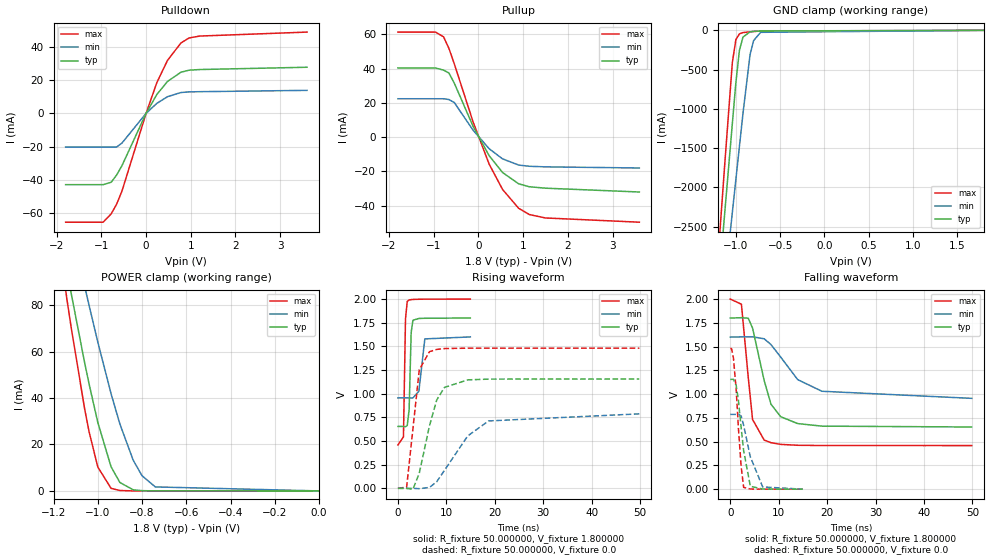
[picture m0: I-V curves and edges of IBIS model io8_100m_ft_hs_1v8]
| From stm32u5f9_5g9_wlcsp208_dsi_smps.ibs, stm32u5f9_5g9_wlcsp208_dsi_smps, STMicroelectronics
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|   Model io8_100m_ft_hs_1v8
[Model]  io8_100m_ft_hs_1v8
Model_type I/O
Polarity   Non-Inverting
Enable   Active-Low
Vinl =   0.540000V
Vinh =   1.260000V
Vmeas =  0.900000V
Cref =   50.000000pF
Rref =   100.000000M
Vref =   0.0V
C_comp   3.148300pF   3.147400pF   3.196500pF
[Temperature Range]   25.000000   0.140000k   -40.000000
[Pullup Reference]   1.800000V   1.600000V   2.000000V
[Pulldown Reference]   0.0V   0.0V   0.0V
[POWER Clamp Reference]   1.800000V   1.600000V   2.000000V
[GND Clamp Reference]   0.0V   0.0V   0.0V
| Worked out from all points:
|   slope of the pulldown table from 0 to 0.27 V, typ, clamps not added: 21.7 ohm
|   slope of the pullup table from 0 to 0.27 V, typ, clamps not added: 22.6 ohm
|   GND clamp passes 1 mA (typ) near -0.51 V on its own axis
|   POWER clamp passes 1 mA (typ) near -0.86 V on its own axis
|   rising waveform, R_fixture 50.000000, V_fixture 1.800000: 20-80 % time 321ps typ, 632ps min, 233ps max; typ from 0.654 V to 1.8 V
|   rising waveform, R_fixture 50.000000, V_fixture 0.0: 20-80 % time 3.21ns typ, 6.76ns min, 1.69ns max; typ from 0 V to 1.16 V
|   falling waveform, R_fixture 50.000000, V_fixture 1.800000: 20-80 % time 3.21ns typ, 6.73ns min, 1.65ns max; typ from 1.8 V to 0.654 V
|   falling waveform, R_fixture 50.000000, V_fixture 0.0: 20-80 % time 1.6ns typ, 2.38ns min, 1.14ns max; typ from 1.16 V to 0 V
[Pulldown]
|Voltage   I(typ)   I(min)   I(max)
-1.8V     -42.74mA   -20.21mA   -65.25mA
-960mV    -42.74mA   -20.21mA   -65.25mA
-780mV    -41.3mA    -20.21mA   -60.25mA
-660mV    -37mA      -20.2mA    -54.5mA
-540mV    -31.39mA   -17.82mA   -46.65mA
0V        0A         0A         10fA
240mV     11.28mA    6.002mA    18.38mA
480mV     19.18mA    10.02mA    31.83mA
780mV     24.67mA    12.5mA     42.21mA
960mV     25.9mA     12.9mA     45.21mA
1.2V      26.29mA    13.01mA    46.37mA
3.6V      27.67mA    13.81mA    48.75mA
[Pullup]
|Voltage   I(typ)   I(min)   I(max)
-1.8V     40.33mA    22.37mA    61.24mA
-960mV    40.33mA    22.37mA    61.24mA
-780mV    39.05mA    22.37mA    58.49mA
-660mV    37.4mA     21.92mA    51.77mA
-540mV    31.51mA    20.18mA    42.78mA
-120mV    6.338mA    4.065mA    8.965mA
240mV     -10.82mA   -6.752mA   -15.73mA
540mV     -20.62mA   -12.68mA   -30.5mA
900mV     -27.22mA   -16.28mA   -41.49mA
1.14V     -28.94mA   -17mA      -45.14mA
1.5V      -29.77mA   -17.34mA   -47.14mA
3.6V      -32mA      -18mA      -49.6mA
[GND_clamp]
|Voltage   I(typ)   I(min)   I(max)
-1.8V     -9.707A    -9.942A    -9.774A
-1.2V     -3.309A    -4.006A    -2.864A
-1.16V    -2.777A    -3.584A    -2.239A
-1.12V    -2.246A    -3.162A    -1.614A
-1.04V    -1.186A    -2.319A    -408.6mA
-1V       -663.9mA   -1.898A    -117.8mA
-960mV    -254mA     -1.478A    -45.14mA
-920mV    -86.03mA   -1.06A     -28.58mA
-840mV    -19.12mA   -308.9mA   -18.74mA
-800mV    -13.39mA   -130.8mA   -15.31mA
-720mV    -7.948mA   -25.37mA   -9.381mA
1.8V      0A         14.97nA    0A
[POWER_clamp]
|Voltage   I(typ)   I(min)   I(max)
-1.8V     470.8mA    433.7mA    554.6mA
-1.14V    95.25mA    122.7mA    82.82mA
-1.12V    84.97mA    114mA      70.27mA
-1.06V    55.51mA    88.42mA    35.67mA
-1.04V    46.34mA    80.15mA    25.76mA
-1V       29.51mA    64.13mA    10.3mA
-940mV    10.39mA    41.86mA    1.109mA
-900mV    3.624mA    28.77mA    182.8uA
-840mV    490.7uA    13.24mA    11.35uA
-800mV    116.8uA    6.532mA    1.77uA
-740mV    13.2uA     1.723mA    109.3nA
0V        0A         18.72nA    0A
[Ramp]
| variable   typ   min   max
dV/dt_r  0.69300/3.20236n   0.47203/6.75416n   0.88872/1.68887n
dV/dt_f  0.68762/3.20647n   0.38659/6.71804n   0.92482/1.65085n
R_load = 50.000000
[Rising Waveform]
R_fixture= 50.000000
V_fixture= 1.800000
V_fixture_min= 1.600000
V_fixture_max= 2.000000
|time   V(typ)   V(min)   V(max)
0s        654mV      955.4mV    458.7mV
1.141ns   653.9mV    955.4mV    543.2mV
1.562ns   650.9mV    955.4mV    1.79V
1.922ns   663.7mV    955.4mV    1.975V
2.312ns   831.7mV    955.4mV    1.99V
2.733ns   1.646V     955.2mV    1.994V
3.093ns   1.776V     954.4mV    1.996V
4.324ns   1.795V     1.026V     1.998V
5.556ns   1.797V     1.579V     1.999V
14.95ns   1.8V       1.6V       2V
[Rising Waveform]
R_fixture= 50.000000
V_fixture= 0.0
V_fixture_min= 0.0
V_fixture_max= 0.0
|time   V(typ)   V(min)   V(max)
0s        3.153uV    2.99uV     1.193uV
1.802ns   -1.584mV   522.9nV    12.74mV
3.103ns   -9.118mV   131.7uV    631.6mV
4.404ns   157.9mV    -4.26mV    1.252V
6.507ns   658.7mV    9.256mV    1.444V
8.008ns   933.8mV    69.31mV    1.468V
9.61ns    1.066V     190mV      1.477V
14.41ns   1.146V     553.5mV    1.481V
18.72ns   1.154V     712mV      1.481V
49.85ns   1.155V     786.8mV    1.481V
[Falling Waveform]
R_fixture= 50.000000
V_fixture= 1.800000
V_fixture_min= 1.600000
V_fixture_max= 2.000000
|time   V(typ)   V(min)   V(max)
0s        1.8V       1.6V       2V
2.302ns   1.804V     1.602V     1.946V
3.704ns   1.799V     1.603V     1.182V
4.605ns   1.695V     1.603V     733.4mV
7.007ns   1.142V     1.582V     516mV
8.408ns   894mV      1.521V     489mV
10.41ns   762.2mV    1.39V      471.2mV
13.91ns   690.1mV    1.153V     461.8mV
18.92ns   663.1mV    1.03V      459.1mV
49.85ns   654mV      955.4mV    458.7mV
[Falling Waveform]
R_fixture= 50.000000
V_fixture= 0.0
V_fixture_min= 0.0
V_fixture_max= 0.0
|time   V(typ)   V(min)   V(max)
0s        1.155V     786.8mV    1.481V
270.3ps   1.155V     786.8mV    1.479V
660.7ps   1.156V     786.8mV    1.376V
1.231ns   1.09V      786.7mV    1.043V
1.682ns   935.3mV    787.7mV    643.2mV
2.252ns   645.8mV    770.1mV    235.1mV
2.763ns   405.4mV    671.5mV    19.03mV
4.144ns   30.19mV    340mV      1.495mV
6.697ns   1.145mV    23.21mV    456.7uV
14.95ns   3.153uV    2.99uV     1.193uV
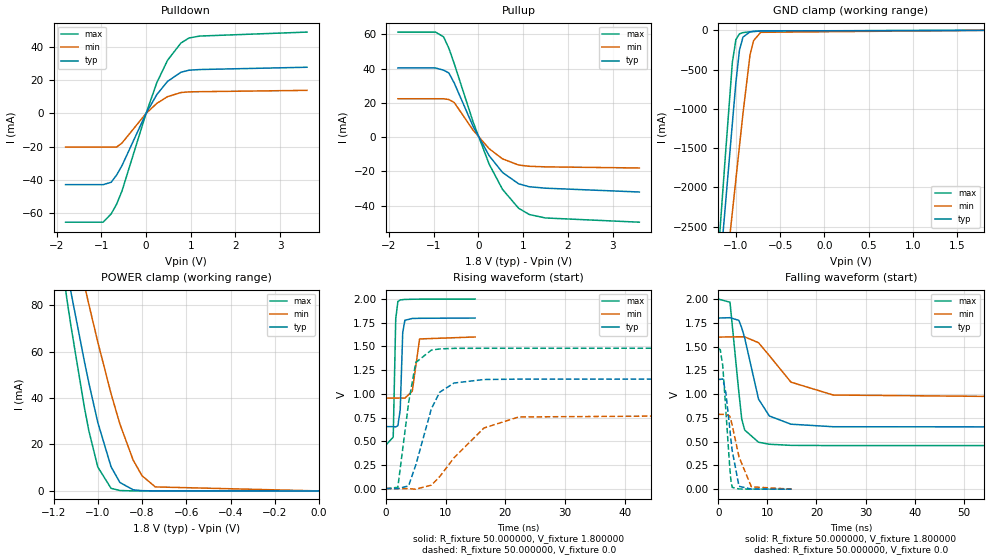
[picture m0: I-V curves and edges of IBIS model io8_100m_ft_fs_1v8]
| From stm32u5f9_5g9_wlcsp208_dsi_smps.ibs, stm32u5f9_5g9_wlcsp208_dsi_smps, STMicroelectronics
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|   Model io8_100m_ft_fs_1v8
[Model]  io8_100m_ft_fs_1v8
Model_type I/O
Polarity   Non-Inverting
Enable   Active-Low
Vinl =   0.540000V
Vinh =   1.260000V
Vmeas =  0.900000V
Cref =   50.000000pF
Rref =   100.000000M
Vref =   0.0V
C_comp   3.148300pF   3.147400pF   3.196500pF
[Temperature Range]   25.000000   0.140000k   -40.000000
[Pullup Reference]   1.800000V   1.600000V   2.000000V
[Pulldown Reference]   0.0V   0.0V   0.0V
[POWER Clamp Reference]   1.800000V   1.600000V   2.000000V
[GND Clamp Reference]   0.0V   0.0V   0.0V
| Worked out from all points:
|   slope of the pulldown table from 0 to 0.27 V, typ, clamps not added: 21.7 ohm
|   slope of the pullup table from 0 to 0.27 V, typ, clamps not added: 22.6 ohm
|   GND clamp passes 1 mA (typ) near -0.51 V on its own axis
|   POWER clamp passes 1 mA (typ) near -0.86 V on its own axis
|   rising waveform, R_fixture 50.000000, V_fixture 1.800000: 20-80 % time 321ps typ, 632ps min, 233ps max; typ from 0.654 V to 1.8 V
|   rising waveform, R_fixture 50.000000, V_fixture 0.0: 20-80 % time 3.21ns typ, 6.76ns min, 1.69ns max; typ from 0 V to 1.16 V
|   falling waveform, R_fixture 50.000000, V_fixture 1.800000: 20-80 % time 3.21ns typ, 6.73ns min, 1.66ns max; typ from 1.8 V to 0.654 V
|   falling waveform, R_fixture 50.000000, V_fixture 0.0: 20-80 % time 1.6ns typ, 2.38ns min, 1.14ns max; typ from 1.16 V to 0 V
[Pulldown]
|Voltage   I(typ)   I(min)   I(max)
-1.8V     -42.74mA   -20.21mA   -65.25mA
-960mV    -42.74mA   -20.21mA   -65.25mA
-780mV    -41.3mA    -20.21mA   -60.25mA
-660mV    -37mA      -20.2mA    -54.5mA
-540mV    -31.39mA   -17.82mA   -46.65mA
0V        0A         0A         10fA
240mV     11.28mA    6.002mA    18.38mA
480mV     19.18mA    10.02mA    31.83mA
780mV     24.67mA    12.5mA     42.21mA
960mV     25.9mA     12.9mA     45.21mA
1.2V      26.29mA    13.01mA    46.37mA
3.6V      27.67mA    13.81mA    48.75mA
[Pullup]
|Voltage   I(typ)   I(min)   I(max)
-1.8V     40.33mA    22.37mA    61.24mA
-960mV    40.33mA    22.37mA    61.24mA
-780mV    39.05mA    22.37mA    58.49mA
-660mV    37.4mA     21.92mA    51.77mA
-540mV    31.51mA    20.18mA    42.78mA
-120mV    6.338mA    4.065mA    8.965mA
240mV     -10.82mA   -6.752mA   -15.73mA
540mV     -20.62mA   -12.68mA   -30.5mA
900mV     -27.22mA   -16.28mA   -41.49mA
1.14V     -28.94mA   -17mA      -45.14mA
1.5V      -29.77mA   -17.34mA   -47.14mA
3.6V      -32mA      -18mA      -49.6mA
[GND_clamp]
|Voltage   I(typ)   I(min)   I(max)
-1.8V     -9.707A    -9.942A    -9.774A
-1.2V     -3.309A    -4.006A    -2.864A
-1.16V    -2.777A    -3.584A    -2.239A
-1.12V    -2.246A    -3.162A    -1.614A
-1.04V    -1.186A    -2.319A    -408.6mA
-1V       -663.9mA   -1.898A    -117.8mA
-960mV    -254mA     -1.478A    -45.14mA
-920mV    -86.03mA   -1.06A     -28.58mA
-840mV    -19.12mA   -308.9mA   -18.74mA
-800mV    -13.39mA   -130.8mA   -15.31mA
-720mV    -7.948mA   -25.37mA   -9.381mA
1.8V      0A         14.97nA    0A
[POWER_clamp]
|Voltage   I(typ)   I(min)   I(max)
-1.8V     470.8mA    433.7mA    554.6mA
-1.14V    95.25mA    122.7mA    82.82mA
-1.12V    84.97mA    114mA      70.27mA
-1.06V    55.51mA    88.42mA    35.67mA
-1.04V    46.34mA    80.15mA    25.76mA
-1V       29.51mA    64.13mA    10.3mA
-940mV    10.39mA    41.86mA    1.109mA
-900mV    3.624mA    28.77mA    182.8uA
-840mV    490.7uA    13.24mA    11.35uA
-800mV    116.8uA    6.532mA    1.77uA
-740mV    13.2uA     1.723mA    109.3nA
0V        0A         18.72nA    0A
[Ramp]
| variable   typ   min   max
dV/dt_r  0.69306/3.20389n   0.47207/6.75528n   0.88872/1.68920n
dV/dt_f  0.68762/3.20632n   0.38677/6.72664n   0.92482/1.65073n
R_load = 50.000000
[Rising Waveform]
R_fixture= 50.000000
V_fixture= 1.800000
V_fixture_min= 1.600000
V_fixture_max= 2.000000
|time   V(typ)   V(min)   V(max)
0s        654mV      955.4mV    458.7mV
1.231ns   653.9mV    955.4mV    543.2mV
1.652ns   650.9mV    955.4mV    1.79V
2.012ns   663.7mV    955.4mV    1.975V
2.402ns   831.7mV    955.4mV    1.99V
2.823ns   1.646V     955.2mV    1.994V
3.183ns   1.776V     954.4mV    1.996V
4.414ns   1.795V     1.026V     1.998V
5.646ns   1.797V     1.579V     1.999V
14.95ns   1.8V       1.6V       2V
[Rising Waveform]
R_fixture= 50.000000
V_fixture= 0.0
V_fixture_min= 0.0
V_fixture_max= 0.0
|time   V(typ)   V(min)   V(max)
0s        3.637uV    3.111uV    2.587uV
2.002ns   -1.584mV   523.3nV    12.74mV
3.804ns   28.7mV     -635.9uV   905.6mV
5.005ns   248.3mV    -6.203mV   1.331V
7.608ns   840.1mV    36.16mV    1.461V
9.009ns   1.017V     125.6mV    1.474V
11.41ns   1.114V     325.4mV    1.48V
16.42ns   1.151V     639.3mV    1.481V
22.22ns   1.155V     755.7mV    1.481V
99.7ns    1.155V     786.8mV    1.481V
[Falling Waveform]
R_fixture= 50.000000
V_fixture= 1.800000
V_fixture_min= 1.600000
V_fixture_max= 2.000000
|time   V(typ)   V(min)   V(max)
0s        1.8V       1.6V       2V
2.402ns   1.804V     1.602V     1.967V
4.204ns   1.776V     1.603V     1.02V
4.805ns   1.695V     1.603V     733.4mV
5.405ns   1.588V     1.602V     621.5mV
8.208ns   948mV      1.541V     494.3mV
10.41ns   770mV      1.405V     472.6mV
14.81ns   683.5mV    1.126V     460.9mV
23.42ns   656.8mV    990.4mV    458.7mV
99.7ns    654mV      955.4mV    458.7mV
[Falling Waveform]
R_fixture= 50.000000
V_fixture= 0.0
V_fixture_min= 0.0
V_fixture_max= 0.0
|time   V(typ)   V(min)   V(max)
0s        1.155V     786.8mV    1.481V
420.4ps   1.155V     786.8mV    1.468V
930.9ps   1.16V      786.8mV    1.298V
1.562ns   1.015V     786.6mV    826.2mV
2.342ns   645.8mV    770.1mV    235.1mV
2.613ns   508.9mV    723.1mV    80.64mV
2.853ns   405.4mV    671.5mV    19.03mV
4.234ns   30.18mV    340mV      1.495mV
6.757ns   1.156mV    24.78mV    463.3uV
14.95ns   3.637uV    3.111uV    2.587uV
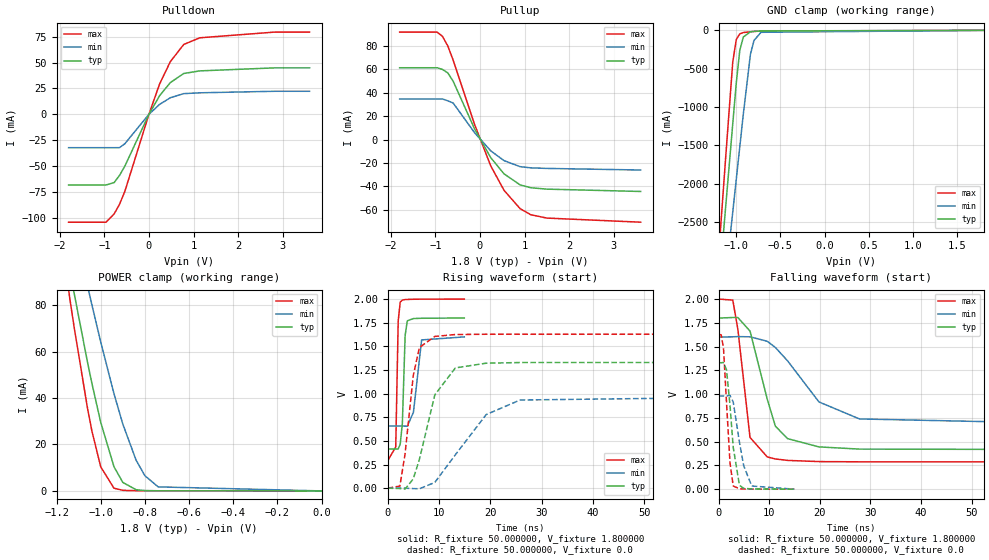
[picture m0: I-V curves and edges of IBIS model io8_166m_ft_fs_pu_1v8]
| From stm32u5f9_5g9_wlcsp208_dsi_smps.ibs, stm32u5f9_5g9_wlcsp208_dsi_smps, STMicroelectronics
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|   Model io8_166m_ft_fs_pu_1v8
[Model]  io8_166m_ft_fs_pu_1v8
Model_type I/O
Polarity   Non-Inverting
Enable   Active-Low
Vinl =   0.540000V
Vinh =   1.260000V
Vmeas =  0.900000V
Cref =   50.000000pF
Rref =   100.000000M
Vref =   0.0V
C_comp   3.358200pF   3.352700pF   3.400300pF
[Temperature Range]   25.000000   0.140000k   -40.000000
[Pullup Reference]   1.800000V   1.600000V   2.000000V
[Pulldown Reference]   0.0V   0.0V   0.0V
[POWER Clamp Reference]   1.800000V   1.600000V   2.000000V
[GND Clamp Reference]   0.0V   0.0V   0.0V
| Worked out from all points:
|   slope of the pulldown table from 0 to 0.27 V, typ, clamps not added: 13.6 ohm
|   slope of the pullup table from 0 to 0.27 V, typ, clamps not added: 15.9 ohm
|   GND clamp passes 1 mA (typ) near -0.51 V on its own axis
|   POWER clamp passes 1 mA (typ) near -0.86 V on its own axis
|   rising waveform, R_fixture 50.000000, V_fixture 1.800000: 20-80 % time 454ps typ, 903ps min, 301ps max; typ from 0.414 V to 1.8 V
|   rising waveform, R_fixture 50.000000, V_fixture 0.0: 20-80 % time 3.64ns typ, 7.99ns min, 1.94ns max; typ from 0 V to 1.33 V
|   falling waveform, R_fixture 50.000000, V_fixture 1.800000: 20-80 % time 3.87ns typ, 9.14ns min, 2.06ns max; typ from 1.8 V to 0.414 V
|   falling waveform, R_fixture 50.000000, V_fixture 0.0: 20-80 % time 1.32ns typ, 1.87ns min, 984ps max; typ from 1.33 V to 0 V
[Pulldown]
|Voltage   I(typ)   I(min)   I(max)
-1.8V     -68.38mA   -32.32mA   -104.4mA
-960mV    -68.38mA   -32.32mA   -104.4mA
-780mV    -66.08mA   -32.32mA   -96.43mA
-660mV    -59.2mA    -32.31mA   -87.22mA
-540mV    -50.22mA   -28.51mA   -74.66mA
0V        0A         0A         0A
240mV     18.04mA    9.6mA      29.42mA
480mV     30.68mA    16.02mA    50.95mA
780mV     39.48mA    19.99mA    67.56mA
1.14V     41.99mA    20.78mA    74.01mA
2.82V     44.92mA    22.27mA    79.53mA
3.6V      44.92mA    22.27mA    79.53mA
[Pullup]
|Voltage   I(typ)   I(min)   I(max)
-1.8V     61.22mA    34.57mA    91.63mA
-960mV    61.22mA    34.57mA    91.63mA
-840mV    59.78mA    34.57mA    88mA
-720mV    56.81mA    33.01mA    79.76mA
-600mV    49.68mA    31.1mA     67.63mA
-120mV    9.014mA    5.781mA    12.75mA
240mV     -15.38mA   -9.6mA     -22.37mA
540mV     -29.31mA   -18.02mA   -43.36mA
900mV     -38.69mA   -23.13mA   -58.99mA
1.14V     -41.14mA   -24.16mA   -64.17mA
1.5V      -42.31mA   -24.64mA   -67mA
3.6V      -44.3mA    -26mA      -70.5mA
[GND_clamp]
|Voltage   I(typ)   I(min)   I(max)
-1.8V     -9.908A    -9.683A    -9.994A
-1.2V     -3.383A    -4.084A    -2.934A
-1.16V    -2.841A    -3.655A    -2.294A
-1.12V    -2.299A    -3.226A    -1.656A
-1.04V    -1.218A    -2.369A    -414.2mA
-1V       -684.7mA   -1.941A    -119.2mA
-960mV    -257.2mA   -1.514A    -45.66mA
-920mV    -87.03mA   -1.089A    -28.93mA
-840mV    -19.35mA   -312.8mA   -18.97mA
-800mV    -13.55mA   -132.4mA   -15.49mA
-720mV    -8.042mA   -25.67mA   -9.491mA
1.8V      0A         13.64nA    0A
[POWER_clamp]
|Voltage   I(typ)   I(min)   I(max)
-1.8V     470.9mA    433.7mA    554.6mA
-1.14V    95.28mA    122.7mA    82.88mA
-1.12V    85mA       114mA      70.34mA
-1.06V    55.55mA    88.43mA    35.73mA
-1.04V    46.38mA    80.17mA    25.83mA
-1V       29.54mA    64.14mA    10.37mA
-940mV    10.43mA    41.88mA    1.177mA
-900mV    3.66mA     28.79mA    250.5uA
-840mV    527.2uA    13.26mA    95.94uA
-800mV    154uA      6.55mA     88.4uA
-740mV    59.84uA    1.741mA    70.38uA
0V        0A         18.18nA    0A
[Ramp]
| variable   typ   min   max
dV/dt_r  0.79757/3.63113n   0.58806/7.98205n   0.97651/1.93368n
dV/dt_f  0.83132/3.86660n   0.56553/9.12592n   1.02743/2.04826n
R_load = 50.000000
[Rising Waveform]
R_fixture= 50.000000
V_fixture= 1.800000
V_fixture_min= 1.600000
V_fixture_max= 2.000000
|time   V(typ)   V(min)   V(max)
0s        414.4mV    657.5mV    287.6mV
1.592ns   413.9mV    657.5mV    436mV
2.072ns   415.6mV    657.5mV    1.767V
2.462ns   464.5mV    657.5mV    1.968V
2.883ns   686.6mV    657.4mV    1.989V
3.423ns   1.615V     656.5mV    1.995V
3.844ns   1.77V      655mV      1.996V
5.045ns   1.794V     804.6mV    1.998V
6.637ns   1.797V     1.568V     1.999V
14.95ns   1.8V       1.6V       2V
[Rising Waveform]
R_fixture= 50.000000
V_fixture= 0.0
V_fixture_min= 0.0
V_fixture_max= 0.0
|time   V(typ)   V(min)   V(max)
0s        427.6uV    510uV      389.5uV
2.402ns   -3.279mV   508.5uV    23.12mV
3.403ns   -9.971mV   612.4uV    361.2mV
5.005ns   98.92mV    -3.813mV   1.191V
6.206ns   305.4mV    -6.052mV   1.488V
9.209ns   987.3mV    61.44mV    1.605V
13.21ns   1.272V     353.7mV    1.625V
19.22ns   1.322V     779.1mV    1.628V
25.83ns   1.329V     932.8mV    1.628V
99.7ns    1.33V      980.7mV    1.628V
[Falling Waveform]
R_fixture= 50.000000
V_fixture= 1.800000
V_fixture_min= 1.600000
V_fixture_max= 2.000000
|time   V(typ)   V(min)   V(max)
0s        1.8V       1.6V       2V
2.803ns   1.806V     1.603V     1.989V
3.804ns   1.806V     1.605V     1.682V
6.206ns   1.663V     1.603V     544.2mV
9.61ns    946.3mV    1.556V     339.6mV
11.21ns   663.2mV    1.491V     318mV
13.61ns   532.2mV    1.351V     303mV
19.82ns   445mV      918mV      290.5mV
27.83ns   421.8mV    739.1mV    288mV
99.7ns    414.4mV    657.5mV    287.6mV
[Falling Waveform]
R_fixture= 50.000000
V_fixture= 0.0
V_fixture_min= 0.0
V_fixture_max= 0.0
|time   V(typ)   V(min)   V(max)
0s        1.33V      980.7mV    1.628V
510.5ps   1.33V      980.7mV    1.624V
961ps     1.333V     980.7mV    1.487V
1.562ns   1.256V     980.5mV    910mV
2.252ns   880.5mV    987.1mV    275.3mV
2.883ns   441.9mV    917.9mV    34.19mV
4.114ns   41.29mV    495.3mV    3.726mV
4.955ns   8.774mV    246.4mV    2.088mV
6.547ns   3.166mV    33.43mV    1.136mV
14.95ns   427.6uV    510uV      389.5uV
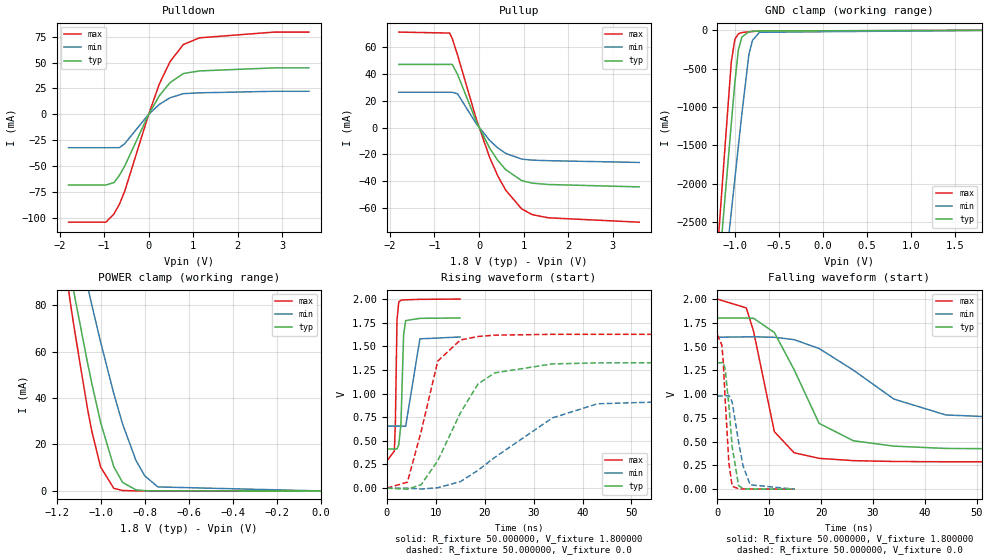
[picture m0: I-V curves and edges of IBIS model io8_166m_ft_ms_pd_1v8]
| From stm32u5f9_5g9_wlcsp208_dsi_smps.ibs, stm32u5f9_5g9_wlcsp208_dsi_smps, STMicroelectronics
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|   Model io8_166m_ft_ms_pd_1v8
[Model]  io8_166m_ft_ms_pd_1v8
Model_type I/O
Polarity   Non-Inverting
Enable   Active-Low
Vinl =   0.540000V
Vinh =   1.260000V
Vmeas =  0.900000V
Cref =   50.000000pF
Rref =   100.000000M
Vref =   0.0V
C_comp   3.358200pF   3.352700pF   3.400300pF
[Temperature Range]   25.000000   0.140000k   -40.000000
[Pullup Reference]   1.800000V   1.600000V   2.000000V
[Pulldown Reference]   0.0V   0.0V   0.0V
[POWER Clamp Reference]   1.800000V   1.600000V   2.000000V
[GND Clamp Reference]   0.0V   0.0V   0.0V
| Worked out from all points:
|   slope of the pulldown table from 0 to 0.27 V, typ, clamps not added: 13.6 ohm
|   slope of the pullup table from 0 to 0.27 V, typ, clamps not added: 15.9 ohm
|   GND clamp passes 1 mA (typ) near -0.50 V on its own axis
|   POWER clamp passes 1 mA (typ) near -0.86 V on its own axis
|   rising waveform, R_fixture 50.000000, V_fixture 1.800000: 20-80 % time 446ps typ, 901ps min, 295ps max; typ from 0.414 V to 1.8 V
|   rising waveform, R_fixture 50.000000, V_fixture 0.0: 20-80 % time 7.87ns typ, 16.8ns min, 4.3ns max; typ from 0 V to 1.33 V
|   falling waveform, R_fixture 50.000000, V_fixture 1.800000: 20-80 % time 7.17ns typ, 17ns min, 3.86ns max; typ from 1.8 V to 0.414 V
|   falling waveform, R_fixture 50.000000, V_fixture 0.0: 20-80 % time 1.31ns typ, 1.88ns min, 977ps max; typ from 1.33 V to 0 V
[Pulldown]
|Voltage   I(typ)   I(min)   I(max)
-1.8V     -68.38mA   -32.32mA   -104.4mA
-960mV    -68.38mA   -32.32mA   -104.4mA
-780mV    -66.08mA   -32.32mA   -96.43mA
-660mV    -59.2mA    -32.31mA   -87.22mA
-540mV    -50.22mA   -28.51mA   -74.66mA
0V        -10fA      -200fA     0A
240mV     18.04mA    9.6mA      29.42mA
480mV     30.68mA    16.02mA    50.95mA
780mV     39.48mA    19.99mA    67.56mA
1.14V     41.99mA    20.78mA    74.01mA
2.82V     44.93mA    22.28mA    79.57mA
3.6V      44.93mA    22.28mA    79.57mA
[Pullup]
|Voltage   I(typ)   I(min)   I(max)
-1.8V     47.02mA    26.28mA    71.1mA
-660mV    47.02mA    26.28mA    70.37mA
-600mV    47.02mA    26.28mA    66.18mA
-480mV    39.45mA    25.02mA    53.78mA
-60mV     4.42mA     2.808mA    6.308mA
240mV     -15.38mA   -9.6mA     -22.37mA
420mV     -24.43mA   -15.12mA   -35.87mA
600mV     -31.41mA   -19.24mA   -46.67mA
960mV     -39.54mA   -23.52mA   -60.64mA
1.2V      -41.44mA   -24.28mA   -64.93mA
1.56V     -42.42mA   -24.69mA   -67.24mA
3.6V      -44.2mA    -26mA      -70.5mA
[GND_clamp]
|Voltage   I(typ)   I(min)   I(max)
-1.8V     -9.908A    -9.683A    -9.994A
-1.2V     -3.383A    -4.084A    -2.934A
-1.16V    -2.841A    -3.655A    -2.294A
-1.12V    -2.299A    -3.226A    -1.656A
-1.04V    -1.218A    -2.369A    -414.2mA
-1V       -684.7mA   -1.941A    -119.2mA
-960mV    -257.2mA   -1.514A    -45.67mA
-920mV    -87.04mA   -1.089A    -28.94mA
-840mV    -19.36mA   -312.8mA   -18.98mA
-800mV    -13.56mA   -132.4mA   -15.51mA
-720mV    -8.053mA   -25.67mA   -9.505mA
1.8V      45.71uA    33.32uA    56.11uA
[POWER_clamp]
|Voltage   I(typ)   I(min)   I(max)
-1.8V     470.8mA    433.7mA    554.6mA
-1.14V    95.25mA    122.7mA    82.82mA
-1.12V    84.97mA    114mA      70.27mA
-1.06V    55.51mA    88.42mA    35.67mA
-1.04V    46.34mA    80.15mA    25.76mA
-1V       29.51mA    64.13mA    10.3mA
-940mV    10.39mA    41.86mA    1.109mA
-900mV    3.624mA    28.77mA    182.8uA
-840mV    490.7uA    13.24mA    11.35uA
-800mV    116.8uA    6.532mA    1.77uA
-740mV    13.2uA     1.724mA    109.3nA
0V        0A         18.75nA    0A
[Ramp]
| variable   typ   min   max
dV/dt_r  0.79740/7.86304n   0.58748/16.72567n   0.97632/4.28847n
dV/dt_f  0.83141/7.16265n   0.56324/16.98232n   1.02745/3.84884n
R_load = 50.000000
[Rising Waveform]
R_fixture= 50.000000
V_fixture= 1.800000
V_fixture_min= 1.600000
V_fixture_max= 2.000000
|time   V(typ)   V(min)   V(max)
0s        413.8mV    656.4mV    287.1mV
1.532ns   413.4mV    656.4mV    391.5mV
1.742ns   412.6mV    656.4mV    686.1mV
2.072ns   415.1mV    656.4mV    1.778V
2.432ns   456.5mV    656.4mV    1.968V
2.883ns   678.9mV    656.3mV    1.988V
3.423ns   1.619V     655.3mV    1.991V
3.844ns   1.772V     653.9mV    1.992V
6.757ns   1.796V     1.579V     1.997V
14.95ns   1.8V       1.599V     2V
[Rising Waveform]
R_fixture= 50.000000
V_fixture= 0.0
V_fixture_min= 0.0
V_fixture_max= 0.0
|time   V(typ)   V(min)   V(max)
0s        2.604uV    2.594uV    1.262uV
4.204ns   -11mV      -767.7uV   63.33mV
7.007ns   36mV       -9.677mV   598.4mV
10.41ns   290.5mV    4.551mV    1.344V
15.02ns   794.6mV    68.45mV    1.567V
18.62ns   1.101V     187.8mV    1.604V
22.02ns   1.219V     324mV      1.618V
33.83ns   1.314V     742.4mV    1.627V
43.04ns   1.325V     892.2mV    1.627V
99.7ns    1.329V     979.8mV    1.627V
[Falling Waveform]
R_fixture= 50.000000
V_fixture= 1.800000
V_fixture_min= 1.600000
V_fixture_max= 2.000000
|time   V(typ)   V(min)   V(max)
0s        1.8V       1.599V     2V
5.606ns   1.8V       1.602V     1.907V
7.007ns   1.798V     1.603V     1.661V
11.01ns   1.648V     1.598V     605.1mV
14.81ns   1.258V     1.573V     383.2mV
19.62ns   692.9mV    1.48V      324.3mV
26.23ns   509.3mV    1.252V     300.1mV
34.03ns   452.8mV    947.9mV    291.3mV
44.04ns   428.4mV    780.6mV    288.1mV
99.7ns    413.8mV    656.4mV    287.1mV
[Falling Waveform]
R_fixture= 50.000000
V_fixture= 0.0
V_fixture_min= 0.0
V_fixture_max= 0.0
|time   V(typ)   V(min)   V(max)
0s        1.329V     979.8mV    1.627V
900.9ps   1.331V     979.8mV    1.516V
1.141ns   1.335V     979.8mV    1.364V
1.532ns   1.265V     979.6mV    952.5mV
2.252ns   884.7mV    986.9mV    273.3mV
2.883ns   447.3mV    918.2mV    31.84mV
4.114ns   37.98mV    498.7mV    3.424mV
4.985ns   4.686mV    244.1mV    2.619mV
6.366ns   1.413mV    45.64mV    1.809mV
14.95ns   2.604uV    2.594uV    1.262uV
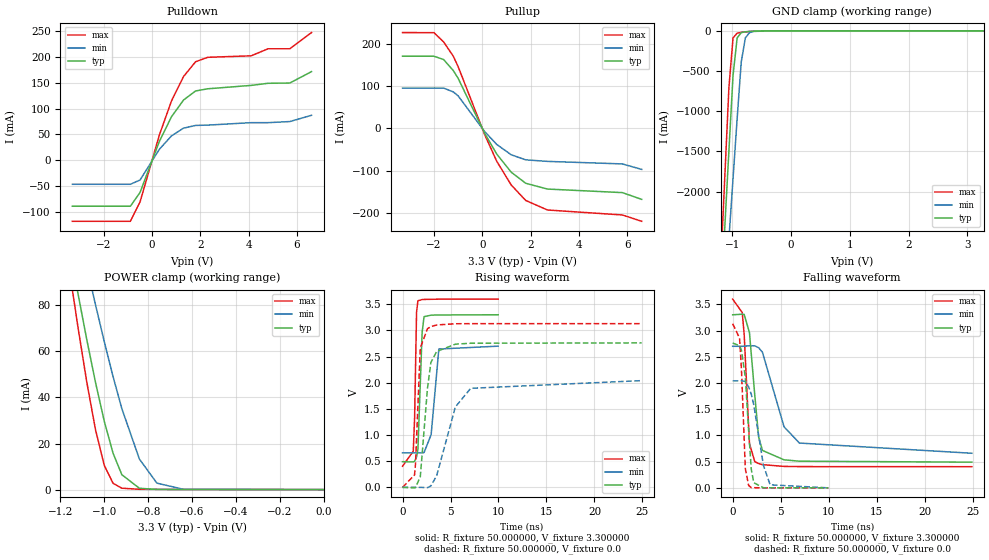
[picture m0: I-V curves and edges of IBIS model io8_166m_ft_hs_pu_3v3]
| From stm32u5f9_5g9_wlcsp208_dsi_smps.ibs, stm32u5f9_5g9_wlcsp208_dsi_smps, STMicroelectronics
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|   Model io8_166m_ft_hs_pu_3v3
[Model]  io8_166m_ft_hs_pu_3v3
Model_type I/O
Polarity   Non-Inverting
Enable   Active-Low
Vinl =   0.990000V
Vinh =   2.310000V
Vmeas =  1.650000V
Cref =   50.000000pF
Rref =   100.000000M
Vref =   0.0V
C_comp   3.517200pF   3.489400pF   3.557800pF
[Temperature Range]   25.000000   0.140000k   -40.000000
[Pullup Reference]   3.300000V   2.700000V   3.600000V
[Pulldown Reference]   0.0V   0.0V   0.0V
[POWER Clamp Reference]   3.300000V   2.700000V   3.600000V
[GND Clamp Reference]   0.0V   0.0V   0.0V
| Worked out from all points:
|   slope of the pulldown table from 0 to 0.495 V, typ, clamps not added: 8.73 ohm
|   slope of the pullup table from 0 to 0.495 V, typ, clamps not added: 9.64 ohm
|   GND clamp passes 1 mA (typ) near -0.50 V on its own axis
|   POWER clamp passes 1 mA (typ) near -0.85 V on its own axis
|   rising waveform, R_fixture 50.000000, V_fixture 3.300000: 20-80 % time 260ps typ, 442ps min, 195ps max; typ from 0.49 V to 3.3 V
|   rising waveform, R_fixture 50.000000, V_fixture 0.0: 20-80 % time 748ps typ, 1.95ns min, 401ps max; typ from 0.001 V to 2.76 V
|   falling waveform, R_fixture 50.000000, V_fixture 3.300000: 20-80 % time 759ps typ, 1.84ns min, 492ps max; typ from 3.3 V to 0.49 V
|   falling waveform, R_fixture 50.000000, V_fixture 0.0: 20-80 % time 576ps typ, 1.09ns min, 397ps max; typ from 2.76 V to 0.001 V
[Pulldown]
|Voltage   I(typ)   I(min)   I(max)
-3.3V     -89.71mA   -47.06mA   -119mA
-900mV    -89.71mA   -47.06mA   -119mA
-500mV    -62.92mA   -38.72mA   -81.44mA
300mV     36.2mA     21.01mA    48.7mA
800mV     84.07mA    46.96mA    114.8mA
1.3V      116.7mA    62.09mA    162.4mA
1.8V      134.4mA    67.39mA    191.2mA
2.3V      138.6mA    67.98mA    199.8mA
4.1V      145.2mA    72.76mA    202.7mA
4.8V      149.3mA    72.76mA    216.4mA
5.7V      149.8mA    74.9mA     216.4mA
6.6V      172mA      87.1mA     247.9mA
[Pullup]
|Voltage   I(typ)   I(min)   I(max)
-3.3V     171.2mA    95.79mA    227.3mA
-2V       171.2mA    95.79mA    227.1mA
-1.6V     163.4mA    95.79mA    205.2mA
-1.2V     137.3mA    86.67mA    171.4mA
-1V       119.1mA    77.38mA    146.9mA
100mV     -11.39mA   -7.258mA   -14.51mA
600mV     -60.65mA   -37.83mA   -77.68mA
1.2V      -103.6mA   -62.35mA   -134mA
1.8V      -129.9mA   -74.33mA   -170.6mA
2.7V      -143.6mA   -78mA      -193.2mA
5.8V      -152mA     -84mA      -205mA
6.6V      -168mA     -97mA      -220mA
[GND_clamp]
|Voltage   I(typ)   I(min)   I(max)
-3.3V     -9.098A    -9.372A    -9.671A
-1.2V     -3.386A    -4.091A    -2.933A
-1.13V    -2.437A    -3.34A     -1.815A
-1.06V    -1.49A     -2.588A    -705.6mA
-990mV    -555.7mA   -1.839A    -89.03mA
-920mV    -88.12mA   -1.093A    -28.78mA
-850mV    -22.35mA   -387.4mA   -19.84mA
-780mV    -12.12mA   -88.01mA   -13.88mA
-710mV    -7.71mA    -22.52mA   -8.846mA
-640mV    -4.545mA   -7.864mA   -4.87mA
-360mV    -31.12uA   -173.5uA   -8.497uA
3.28V     0A         14.15nA    -7.901nA
[POWER_clamp]
|Voltage   I(typ)   I(min)   I(max)
-3.28V    1.355A     1.167A     1.665A
-1.16V    105.8mA    131.6mA    95.87mA
-1.12V    85.08mA    114mA      70.45mA
-1.08V    65.17mA    96.88mA    46.74mA
-1.04V    46.48mA    80.2mA     25.96mA
-1V       29.63mA    64.18mA    10.49mA
-960mV    15.81mA    49.06mA    2.743mA
-920mV    6.481mA    35.16mA    612.1uA
-840mV    577.5uA    13.29mA    137.6uA
-760mV    93.73uA    2.807mA    97.77uA
-640mV    40.05uA    158.9uA    59.33uA
0V        0A         19.33nA    0A
[Ramp]
| variable   typ   min   max
dV/dt_r  1.65687/0.74668n   1.22430/1.94617n   1.87825/0.39960n
dV/dt_f  1.68571/0.75800n   1.22316/1.83501n   1.91753/0.49015n
R_load = 50.000000
[Rising Waveform]
R_fixture= 50.000000
V_fixture= 3.300000
V_fixture_min= 2.700000
V_fixture_max= 3.600000
|time   V(typ)   V(min)   V(max)
0s        490.5mV    660.4mV    404.1mV
1.121ns   486.2mV    660.4mV    692.8mV
1.261ns   498.3mV    660.4mV    1.346V
1.461ns   582.8mV    660.3mV    3.348V
1.602ns   722.3mV    660.2mV    3.568V
2.042ns   2.962V     658.4mV    3.591V
2.242ns   3.263V     665.5mV    3.593V
2.983ns   3.293V     1.009V     3.596V
3.784ns   3.296V     2.645V     3.598V
9.97ns    3.3V       2.7V       3.599V
[Rising Waveform]
R_fixture= 50.000000
V_fixture= 0.0
V_fixture_min= 0.0
V_fixture_max= 0.0
|time   V(typ)   V(min)   V(max)
0s        561.3uV    599.8uV    579.7uV
1.251ns   -9.258mV   633.7uV    237.5mV
1.351ns   -4.316mV   649.8uV    439.9mV
1.852ns   203.5mV    185.1uV    2.669V
2.603ns   1.9V       -5.68mV    3.035V
2.953ns   2.386V     27.65mV    3.073V
3.554ns   2.597V     221mV      3.105V
5.506ns   2.738V     1.538V     3.128V
7.107ns   2.756V     1.894V     3.13V
24.92ns   2.762V     2.041V     3.131V
[Falling Waveform]
R_fixture= 50.000000
V_fixture= 3.300000
V_fixture_min= 2.700000
V_fixture_max= 3.600000
|time   V(typ)   V(min)   V(max)
0s        3.3V       2.7V       3.599V
1.001ns   3.312V     2.699V     3.342V
1.201ns   3.307V     2.702V     2.925V
1.752ns   2.959V     2.71V      844.3mV
2.302ns   1.775V     2.709V     501.8mV
2.703ns   972.8mV    2.673V     463.9mV
3.103ns   714.7mV    2.587V     443.1mV
5.355ns   534.9mV    1.165V     409.9mV
6.957ns   509.1mV    854.8mV    406mV
24.92ns   490.5mV    660.4mV    404.1mV
[Falling Waveform]
R_fixture= 50.000000
V_fixture= 0.0
V_fixture_min= 0.0
V_fixture_max= 0.0
|time   V(typ)   V(min)   V(max)
0s        2.762V     2.041V     3.131V
720.7ps   2.711V     2.041V     2.854V
920.9ps   2.621V     2.042V     2.244V
1.321ns   2.104V     2.03V      364.1mV
1.662ns   1.102V     1.928V     46.78mV
1.942ns   350.7mV    1.785V     5.634mV
2.202ns   97.79mV    1.582V     3.667mV
3.203ns   3.255mV    433.6mV    1.899mV
3.904ns   2.171mV    58.52mV    1.478mV
9.97ns    561.3uV    599.8uV    579.7uV
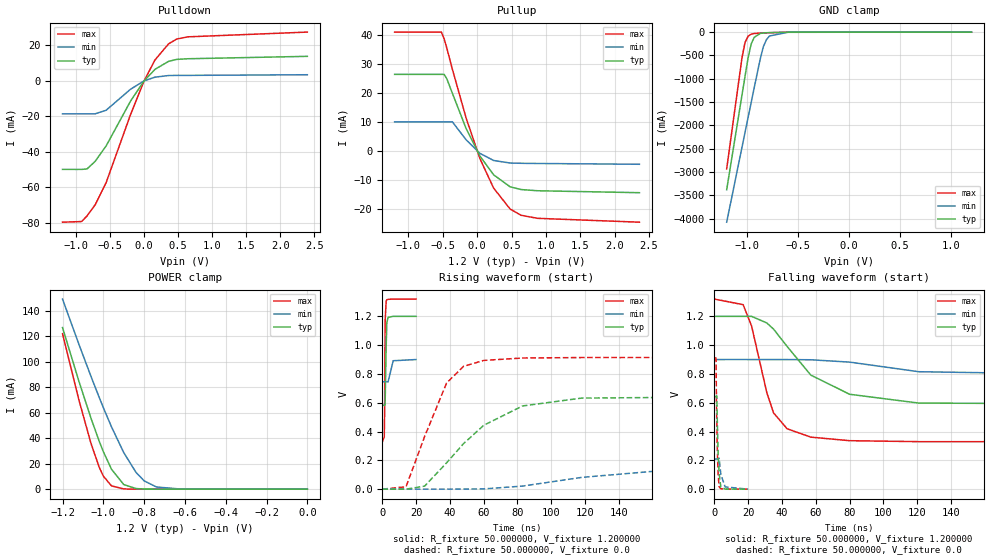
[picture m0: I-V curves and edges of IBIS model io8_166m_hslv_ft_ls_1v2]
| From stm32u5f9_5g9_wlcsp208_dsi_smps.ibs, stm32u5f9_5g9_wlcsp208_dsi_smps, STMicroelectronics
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|   Model io8_166m_hslv_ft_ls_1v2
[Model]  io8_166m_hslv_ft_ls_1v2
Model_type I/O
Polarity   Non-Inverting
Enable   Active-Low
Vinl =   0.360000V
Vinh =   0.840000V
Vmeas =  0.600000V
Cref =   50.000000pF
Rref =   100.000000M
Vref =   0.0V
C_comp   3.151600pF   3.087200pF   3.197800pF
[Temperature Range]   25.000000   0.140000k   -40.000000
[Pullup Reference]   1.200000V   0.900000V   1.320000V
[Pulldown Reference]   0.0V   0.0V   0.0V
[POWER Clamp Reference]   1.200000V   0.900000V   1.320000V
[GND Clamp Reference]   0.0V   0.0V   0.0V
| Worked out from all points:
|   slope of the pulldown table from 0 to 0.18 V, typ, clamps not added: 25.4 ohm
|   slope of the pullup table from 0 to 0.18 V, typ, clamps not added: 27.8 ohm
|   GND clamp passes 1 mA (typ) near -0.51 V on its own axis
|   POWER clamp passes 1 mA (typ) near -0.86 V on its own axis
|   rising waveform, R_fixture 50.000000, V_fixture 1.200000: 20-80 % time 538ps typ, 1.37ns min, 302ps max; typ from 0.582 V to 1.2 V
|   rising waveform, R_fixture 50.000000, V_fixture 0.0: 20-80 % time 35.4ns typ, 87.8ns min, 17.9ns max; typ from 0 V to 0.643 V
|   falling waveform, R_fixture 50.000000, V_fixture 1.200000: 20-80 % time 31.1ns typ, 74.2ns min, 12.9ns max; typ from 1.2 V to 0.582 V
|   falling waveform, R_fixture 50.000000, V_fixture 0.0: 20-80 % time 1.03ns typ, 1.73ns min, 820ps max; typ from 0.643 V to 0 V
[Pulldown]
|Voltage   I(typ)   I(min)   I(max)
-1.2V     -49.86mA   -18.56mA   -79.57mA
-920mV    -49.86mA   -18.56mA   -79.2mA
-840mV    -49.6mA    -18.56mA   -76.08mA
-720mV    -45.32mA   -18.56mA   -69.74mA
-560mV    -36.71mA   -16.58mA   -57.44mA
-200mV    -11.43mA   -4.738mA   -19.03mA
0V        10fA       -1.1pA     0A
160mV     6.476mA    2.074mA    11.78mA
360mV     10.99mA    2.988mA    20.81mA
480mV     12.07mA    3.052mA    23.53mA
640mV     12.43mA    3.072mA    24.76mA
2.4V      13.79mA    3.432mA    27.44mA
[Pullup]
|Voltage   I(typ)   I(min)   I(max)
-1.2V     26.49mA    10.13mA    41.07mA
-520mV    26.49mA    10.13mA    41.07mA
-480mV    26.49mA    10.13mA    38.77mA
-440mV    24.94mA    10.13mA    35.49mA
-360mV    19.99mA    10.13mA    28.26mA
-160mV    7.809mA    3.929mA    11.44mA
40mV      -1.649mA   -721uA     -2.521mA
240mV     -8.14mA    -3.199mA   -12.72mA
480mV     -12.27mA   -4.076mA   -19.94mA
640mV     -13.22mA   -4.166mA   -22.09mA
880mV     -13.63mA   -4.229mA   -23.14mA
2.36V     -14.3mA    -4.5mA     -24.47mA
[GND_clamp]
|Voltage   I(typ)   I(min)   I(max)
-1.2V     -3.379A    -4.076A    -2.932A
-1.05V    -1.35A     -2.47A     -550.7mA
-1.02V    -947.8mA   -2.149A    -221.5mA
-990mV    -552.4mA   -1.829A    -88.44mA
-960mV    -255.3mA   -1.51A     -44.87mA
-930mV    -111.8mA   -1.191A    -30.68mA
-870mV    -28.36mA   -564.6mA   -21.34mA
-840mV    -18.65mA   -309.5mA   -18.49mA
-810mV    -14.07mA   -161.6mA   -15.92mA
-780mV    -11.37mA   -83.33mA   -13.53mA
-600mV    -3.009mA   -4.322mA   -3.091mA
1.2V      0A         13.65nA    0A
[POWER_clamp]
|Voltage   I(typ)   I(min)   I(max)
-1.2V     127mA      149.4mA    122.2mA
-1.12V    84.97mA    114mA      70.27mA
-1.06V    55.51mA    88.42mA    35.67mA
-1.02V    37.63mA    72.04mA    17.17mA
-1V       29.51mA    64.13mA    10.3mA
-960mV    15.69mA    48.99mA    2.571mA
-900mV    3.624mA    28.77mA    182.8uA
-840mV    490.7uA    13.24mA    11.35uA
-800mV    116.8uA    6.532mA    1.77uA
-740mV    13.2uA     1.723mA    109.1nA
-620mV    167.4nA    79.36uA    0A
0V        0A         17.87nA    0A
[Ramp]
| variable   typ   min   max
dV/dt_r  0.38561/35.31188n   0.12536/87.70478n   0.54823/17.87288n
dV/dt_f  0.37086/31.04594n   92.38800m/74.07611n 0.59438/12.83670n
R_load = 50.000000
[Rising Waveform]
R_fixture= 50.000000
V_fixture= 1.200000
V_fixture_min= 0.900000
V_fixture_max= 1.320000
|time   V(typ)   V(min)   V(max)
0s        581.9mV    746mV      329.4mV
1.121ns   582mV      746mV      361.3mV
1.321ns   579.3mV    746mV      515.1mV
1.562ns   586.1mV    746mV      1.018V
1.682ns   618.8mV    746mV      1.176V
2.242ns   982.9mV    746mV      1.305V
2.643ns   1.153V     746.1mV    1.315V
3.363ns   1.193V     743.9mV    1.318V
6.406ns   1.2V       891.7mV    1.32V
19.94ns   1.2V       900mV      1.32V
[Rising Waveform]
R_fixture= 50.000000
V_fixture= 0.0
V_fixture_min= 0.0
V_fixture_max= 0.0
|time   V(typ)   V(min)   V(max)
0s        1.999nV    239.3nV    1.184nV
14.01ns   -238.2uV   -104uV     16.17mV
25.03ns   20.94mV    -77.14uV   365.1mV
38.04ns   182.5mV    99.53uV    736.8mV
48.05ns   315.5mV    341.6uV    852.5mV
60.06ns   443.5mV    1.614mV    893.9mV
83.08ns   577.8mV    21.21mV    910.7mV
118.1ns   632.3mV    81.61mV    913.8mV
231.2ns   642.6mV    193.7mV    913.7mV
498.5ns   642.7mV    209.1mV    913.8mV
[Falling Waveform]
R_fixture= 50.000000
V_fixture= 1.200000
V_fixture_min= 0.900000
V_fixture_max= 1.320000
|time   V(typ)   V(min)   V(max)
0s        1.2V       900mV      1.32V
17.02ns   1.2V       900.3mV    1.281V
22.02ns   1.2V       900mV      1.132V
31.03ns   1.154V     900mV      670.1mV
35.04ns   1.111V     900mV      529.1mV
43.04ns   991.2mV    900mV      419.4mV
57.06ns   792.2mV    898.5mV    361.4mV
80.08ns   658.9mV    882.2mV    336.6mV
121.1ns   597.6mV    815.5mV    329.9mV
498.5ns   581.9mV    746mV      329.4mV
[Falling Waveform]
R_fixture= 50.000000
V_fixture= 0.0
V_fixture_min= 0.0
V_fixture_max= 0.0
|time   V(typ)   V(min)   V(max)
0s        642.7mV    209.1mV    913.8mV
920.9ps   643mV      209.2mV    909.8mV
1.241ns   648.8mV    209.3mV    573.8mV
1.401ns   646.6mV    209.3mV    461.7mV
1.722ns   457.9mV    209.3mV    270.5mV
2.162ns   251.3mV    209.1mV    108.1mV
2.763ns   112mV      215.5mV    16.89mV
3.804ns   12.38mV    101.8mV    2.957mV
6.326ns   768.1uV    15.79mV    337.6uV
19.94ns   1.999nV    239.3nV    1.184nV
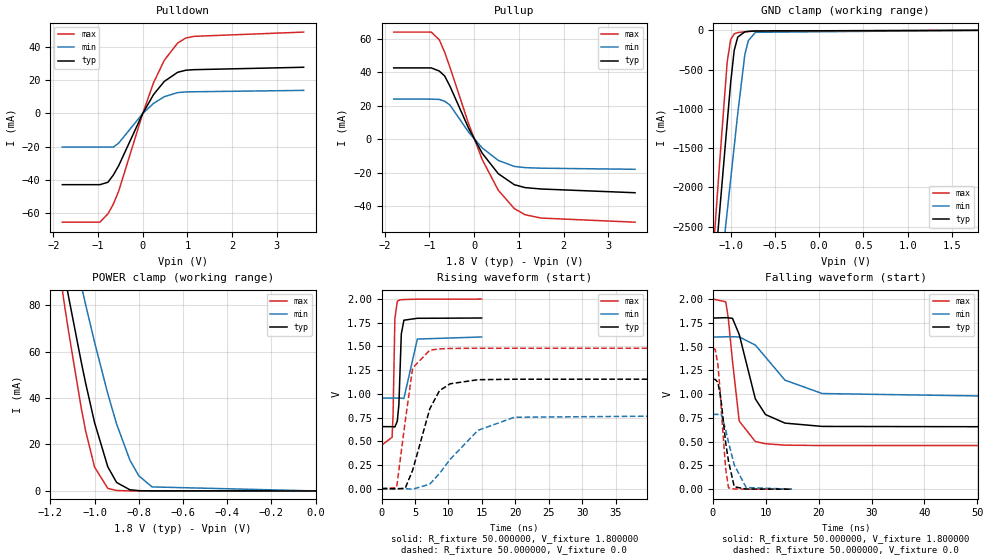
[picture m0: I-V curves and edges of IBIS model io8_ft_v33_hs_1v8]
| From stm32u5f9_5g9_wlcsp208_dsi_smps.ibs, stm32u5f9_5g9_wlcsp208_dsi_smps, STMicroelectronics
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|   Model io8_ft_v33_hs_1v8
[Model]  io8_ft_v33_hs_1v8
Model_type I/O
Polarity   Non-Inverting
Enable   Active-Low
Vinl =   0.540000V
Vinh =   1.260000V
Vmeas =  0.900000V
Cref =   50.000000pF
Rref =   100.000000M
Vref =   0.0V
C_comp   3.087500pF   3.086600pF   3.135700pF
[Temperature Range]   25.000000   0.140000k   -40.000000
[Pullup Reference]   1.800000V   1.600000V   2.000000V
[Pulldown Reference]   0.0V   0.0V   0.0V
[POWER Clamp Reference]   1.800000V   1.600000V   2.000000V
[GND Clamp Reference]   0.0V   0.0V   0.0V
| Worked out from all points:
|   slope of the pulldown table from 0 to 0.27 V, typ, clamps not added: 21.7 ohm
|   slope of the pullup table from 0 to 0.27 V, typ, clamps not added: 22.6 ohm
|   GND clamp passes 1 mA (typ) near -0.51 V on its own axis
|   POWER clamp passes 1 mA (typ) near -0.86 V on its own axis
|   rising waveform, R_fixture 50.000000, V_fixture 1.800000: 20-80 % time 317ps typ, 629ps min, 229ps max; typ from 0.654 V to 1.8 V
|   rising waveform, R_fixture 50.000000, V_fixture 0.0: 20-80 % time 2.89ns typ, 6.11ns min, 1.52ns max; typ from 0 V to 1.16 V
|   falling waveform, R_fixture 50.000000, V_fixture 1.800000: 20-80 % time 3.27ns typ, 6.78ns min, 1.71ns max; typ from 1.8 V to 0.654 V
|   falling waveform, R_fixture 50.000000, V_fixture 0.0: 20-80 % time 1.6ns typ, 2.38ns min, 1.14ns max; typ from 1.16 V to 0 V
[Pulldown]
|Voltage   I(typ)   I(min)   I(max)
-1.8V     -42.74mA   -20.21mA   -65.25mA
-960mV    -42.74mA   -20.21mA   -65.25mA
-780mV    -41.3mA    -20.21mA   -60.25mA
-660mV    -37mA      -20.2mA    -54.5mA
-540mV    -31.39mA   -17.82mA   -46.65mA
0V        -10fA      0A         10fA
240mV     11.28mA    6.002mA    18.38mA
480mV     19.18mA    10.02mA    31.83mA
780mV     24.67mA    12.5mA     42.21mA
960mV     25.9mA     12.9mA     45.21mA
1.14V     26.24mA    12.99mA    46.23mA
3.6V      27.69mA    13.82mA    48.79mA
[Pullup]
|Voltage   I(typ)   I(min)   I(max)
-1.8V     42.59mA    23.91mA    63.98mA
-960mV    42.59mA    23.91mA    63.98mA
-780mV    40.7mA     23.74mA    59.39mA
-660mV    37.78mA    22.66mA    52mA
-540mV    31.58mA    20.35mA    42.82mA
-120mV    6.338mA    4.065mA    8.965mA
180mV     -8.368mA   -5.234mA   -12.14mA
540mV     -20.62mA   -12.68mA   -30.5mA
900mV     -27.22mA   -16.28mA   -41.49mA
1.14V     -28.94mA   -17mA      -45.14mA
1.5V      -29.77mA   -17.34mA   -47.14mA
3.6V      -32mA      -18mA      -49.6mA
[GND_clamp]
|Voltage   I(typ)   I(min)   I(max)
-1.8V     -9.707A    -9.942A    -9.774A
-1.2V     -3.309A    -4.006A    -2.864A
-1.16V    -2.777A    -3.584A    -2.239A
-1.12V    -2.246A    -3.162A    -1.614A
-1.04V    -1.186A    -2.319A    -408.6mA
-1V       -663.9mA   -1.898A    -117.8mA
-960mV    -254mA     -1.478A    -45.14mA
-920mV    -86.03mA   -1.06A     -28.58mA
-840mV    -19.12mA   -308.9mA   -18.74mA
-800mV    -13.39mA   -130.8mA   -15.31mA
-720mV    -7.948mA   -25.37mA   -9.381mA
1.8V      0A         14.97nA    0A
[POWER_clamp]
|Voltage   I(typ)   I(min)   I(max)
-1.8V     470.8mA    433.7mA    554.6mA
-1.14V    95.25mA    122.7mA    82.82mA
-1.12V    84.97mA    114mA      70.27mA
-1.06V    55.51mA    88.42mA    35.67mA
-1.04V    46.34mA    80.15mA    25.76mA
-1V       29.51mA    64.13mA    10.3mA
-940mV    10.39mA    41.86mA    1.109mA
-900mV    3.624mA    28.77mA    182.8uA
-840mV    490.7uA    13.24mA    11.35uA
-800mV    116.8uA    6.532mA    1.77uA
-740mV    13.2uA     1.723mA    109.3nA
0V        0A         18.72nA    0A
[Ramp]
| variable   typ   min   max
dV/dt_r  0.69306/2.88612n   0.47206/6.10562n   0.88872/1.51791n
dV/dt_f  0.68762/3.26455n   0.38677/6.76901n   0.92482/1.71019n
R_load = 50.000000
[Rising Waveform]
R_fixture= 50.000000
V_fixture= 1.800000
V_fixture_min= 1.600000
V_fixture_max= 2.000000
|time   V(typ)   V(min)   V(max)
0s        654mV      955.4mV    458.7mV
1.562ns   653.4mV    955.4mV    541.2mV
1.712ns   652.2mV    955.4mV    779.4mV
1.982ns   650.8mV    955.4mV    1.792V
2.342ns   710.5mV    955.4mV    1.976V
2.583ns   885.5mV    955.2mV    1.988V
2.943ns   1.631V     954.3mV    1.993V
3.333ns   1.777V     951.4mV    1.995V
5.345ns   1.797V     1.578V     1.999V
14.95ns   1.8V       1.6V       2V
[Rising Waveform]
R_fixture= 50.000000
V_fixture= 0.0
V_fixture_min= 0.0
V_fixture_max= 0.0
|time   V(typ)   V(min)   V(max)
0s        4.578uV    -1.127uV   13.19uV
2.242ns   -3.065mV   5.746uV    10.23mV
3.524ns   3.052mV    -686.1uV   709.3mV
4.645ns   194.7mV    -6.054mV   1.274V
7.207ns   841.9mV    46.63mV    1.461V
8.649ns   1.033V     159.2mV    1.474V
10.25ns   1.106V     308.4mV    1.479V
14.41ns   1.149V     614.6mV    1.481V
19.86ns   1.154V     752.7mV    1.481V
79.76ns   1.155V     786.8mV    1.481V
[Falling Waveform]
R_fixture= 50.000000
V_fixture= 1.800000
V_fixture_min= 1.600000
V_fixture_max= 2.000000
|time   V(typ)   V(min)   V(max)
0s        1.8V       1.6V       2V
2.402ns   1.804V     1.603V     1.971V
2.883ns   1.803V     1.603V     1.807V
3.684ns   1.797V     1.603V     1.349V
4.965ns   1.627V     1.602V     716mV
8.008ns   950.4mV    1.516V     501.2mV
9.93ns    785mV      1.39V      477.7mV
13.61ns   695mV      1.147V     463.1mV
20.66ns   660.1mV    1.006V     459mV
79.76ns   654mV      955.4mV    458.7mV
[Falling Waveform]
R_fixture= 50.000000
V_fixture= 0.0
V_fixture_min= 0.0
V_fixture_max= 0.0
|time   V(typ)   V(min)   V(max)
0s        1.155V     786.8mV    1.481V
420.4ps   1.155V     786.8mV    1.472V
930.9ps   1.124V     786.6mV    1.308V
1.351ns   998.6mV    791.6mV    1.035V
1.622ns   888.9mV    779.7mV    787.5mV
2.402ns   487.2mV    625.4mV    213.2mV
2.943ns   291.3mV    491mV      13.06mV
4.024ns   25.45mV    255.7mV    1.782mV
6.276ns   1.312mV    17.13mV    588.2uV
14.95ns   4.578uV    -1.127uV   13.19uV
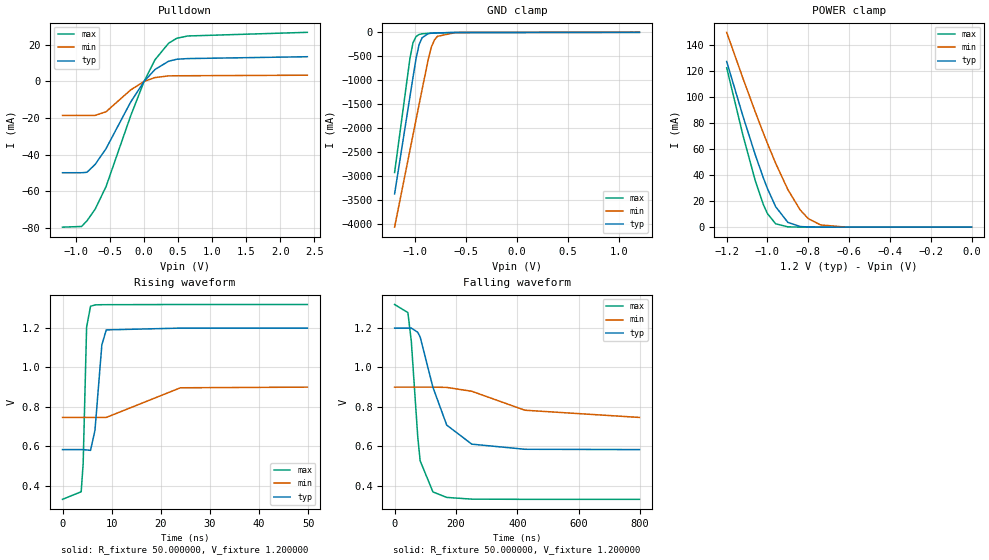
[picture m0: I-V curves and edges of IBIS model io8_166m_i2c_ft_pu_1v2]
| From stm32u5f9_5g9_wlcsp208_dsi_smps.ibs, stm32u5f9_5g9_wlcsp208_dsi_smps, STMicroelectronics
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|   Model io8_166m_i2c_ft_pu_1v2
[Model]  io8_166m_i2c_ft_pu_1v2
Model_type I/O_open_drain
Polarity   Non-Inverting
Enable   Active-Low
Vinl =   0.360000V
Vinh =   0.840000V
Vmeas =  0.600000V
Cref =   50.000000pF
Rref =   100.000000M
Vref =   0.600000V
C_comp   3.158100pF   3.093400pF   3.204300pF
[Temperature Range]   25.000000   0.140000k   -40.000000
[Pullup Reference]   1.200000V   0.900000V   1.320000V
[Pulldown Reference]   0.0V   0.0V   0.0V
[POWER Clamp Reference]   1.200000V   0.900000V   1.320000V
[GND Clamp Reference]   0.0V   0.0V   0.0V
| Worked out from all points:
|   slope of the pulldown table from 0 to 0.18 V, typ, clamps not added: 25.4 ohm
|   GND clamp passes 1 mA (typ) near -0.51 V on its own axis
|   POWER clamp passes 1 mA (typ) near -0.86 V on its own axis
|   rising waveform, R_fixture 50.000000, V_fixture 1.200000: 20-80 % time 1.13ns typ, 3.03ns min, 554ps max; typ from 0.583 V to 1.2 V
|   falling waveform, R_fixture 50.000000, V_fixture 1.200000: 20-80 % time 70.8ns typ, 181ns min, 28.1ns max; typ from 1.2 V to 0.583 V
[Pulldown]
|Voltage   I(typ)   I(min)   I(max)
-1.2V     -49.86mA   -18.57mA   -79.56mA
-920mV    -49.86mA   -18.57mA   -79.19mA
-840mV    -49.6mA    -18.57mA   -76.08mA
-720mV    -45.32mA   -18.57mA   -69.74mA
-560mV    -36.71mA   -16.58mA   -57.44mA
-200mV    -11.43mA   -4.74mA    -19.03mA
0V        0A         0A         0A
160mV     6.477mA    2.075mA    11.78mA
360mV     10.99mA    2.989mA    20.81mA
480mV     12.07mA    3.054mA    23.52mA
640mV     12.43mA    3.074mA    24.76mA
2.4V      13.45mA    3.36mA     26.76mA
[GND_clamp]
|Voltage   I(typ)   I(min)   I(max)
-1.2V     -3.379A    -4.076A    -2.932A
-1.05V    -1.35A     -2.47A     -550.7mA
-1.02V    -947.8mA   -2.149A    -221.5mA
-990mV    -552.4mA   -1.829A    -88.44mA
-960mV    -255.3mA   -1.51A     -44.87mA
-930mV    -111.8mA   -1.191A    -30.68mA
-870mV    -28.36mA   -564.6mA   -21.34mA
-840mV    -18.65mA   -309.5mA   -18.49mA
-810mV    -14.07mA   -161.6mA   -15.92mA
-780mV    -11.37mA   -83.33mA   -13.53mA
-600mV    -3.009mA   -4.322mA   -3.091mA
1.2V      0A         13.65nA    0A
[POWER_clamp]
|Voltage   I(typ)   I(min)   I(max)
-1.2V     127mA      149.4mA    122.2mA
-1.12V    84.98mA    114mA      70.29mA
-1.06V    55.52mA    88.42mA    35.69mA
-1.02V    37.64mA    72.04mA    17.19mA
-1V       29.52mA    64.13mA    10.33mA
-960mV    15.7mA     48.99mA    2.596mA
-900mV    3.636mA    28.77mA    207.8uA
-840mV    502.9uA    13.24mA    43.46uA
-800mV    129uA      6.535mA    43.46uA
-740mV    26.28uA    1.726mA    43.46uA
-620mV    25.1uA     82.34uA    35.72uA
0V        0A         17.36nA    0A
[Ramp]
| variable   typ   min   max
dV/dt_r  0.37031/1.12380n   92.28600m/3.02458n  0.59387/0.54811n
dV/dt_f  0.37042/70.73238n   90.99000m/0.18226u  0.59405/28.07363n
R_load = 50.000000
[Rising Waveform]
R_fixture= 50.000000
V_fixture= 1.200000
V_fixture_min= 0.900000
V_fixture_max= 1.320000
|time   V(typ)   V(min)   V(max)
0s        582.6mV    746.1mV    329.9mV
3.804ns   582.7mV    746.1mV    368.5mV
4.204ns   582.7mV    746.1mV    512.9mV
4.905ns   581.1mV    746.1mV    1.205V
5.706ns   578.7mV    746.1mV    1.311V
6.607ns   680.6mV    746.1mV    1.318V
8.008ns   1.115V     746.1mV    1.319V
8.909ns   1.191V     746.1mV    1.319V
24.02ns   1.2V       896.8mV    1.32V
49.85ns   1.2V       900mV      1.32V
[Falling Waveform]
R_fixture= 50.000000
V_fixture= 1.200000
V_fixture_min= 0.900000
V_fixture_max= 1.320000
|time   V(typ)   V(min)   V(max)
0s        1.2V       900mV      1.32V
43.24ns   1.2V       900mV      1.279V
54.45ns   1.2V       900mV      1.133V
75.28ns   1.179V     900mV      650.2mV
83.28ns   1.155V     900mV      525.6mV
124.9ns   899.2mV    900mV      367.5mV
169.8ns   707.1mV    898.7mV    339.6mV
251.5ns   610.3mV    879mV      330.9mV
424.4ns   584.3mV    782.7mV    329.9mV
797.6ns   582.6mV    746.1mV    329.9mV
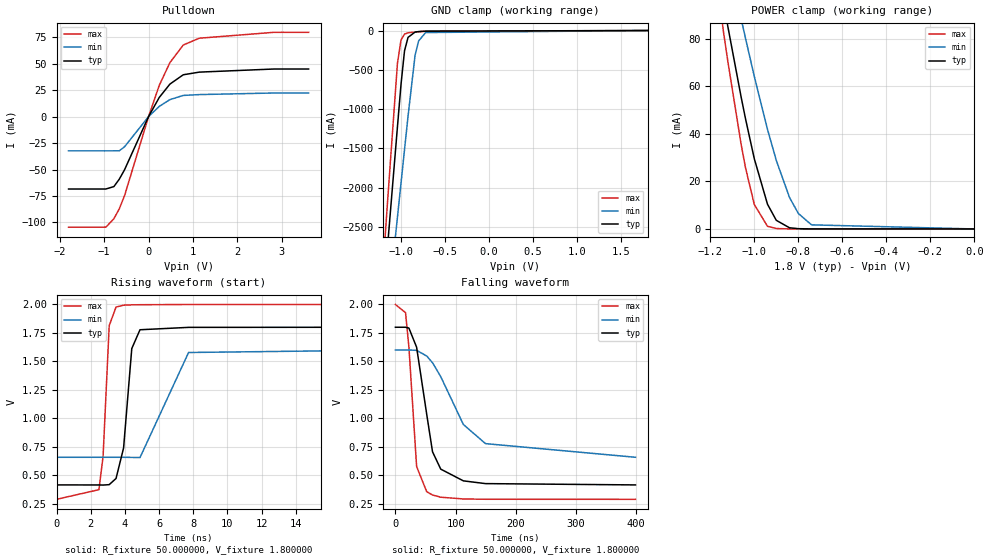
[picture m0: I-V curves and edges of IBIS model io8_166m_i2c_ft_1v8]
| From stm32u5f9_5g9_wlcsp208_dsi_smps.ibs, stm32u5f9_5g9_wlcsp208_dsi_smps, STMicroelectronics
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|   Model io8_166m_i2c_ft_1v8
[Model]  io8_166m_i2c_ft_1v8
Model_type I/O_open_drain
Polarity   Non-Inverting
Enable   Active-Low
Vinl =   0.540000V
Vinh =   1.260000V
Vmeas =  0.900000V
Cref =   50.000000pF
Rref =   100.000000M
Vref =   0.900000V
C_comp   3.364500pF   3.359200pF   3.406800pF
[Temperature Range]   25.000000   0.140000k   -40.000000
[Pullup Reference]   1.800000V   1.600000V   2.000000V
[Pulldown Reference]   0.0V   0.0V   0.0V
[POWER Clamp Reference]   1.800000V   1.600000V   2.000000V
[GND Clamp Reference]   0.0V   0.0V   0.0V
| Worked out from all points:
|   slope of the pulldown table from 0 to 0.27 V, typ, clamps not added: 13.6 ohm
|   GND clamp passes 1 mA (typ) near -0.51 V on its own axis
|   POWER clamp passes 1 mA (typ) near -0.86 V on its own axis
|   rising waveform, R_fixture 50.000000, V_fixture 1.800000: 20-80 % time 443ps typ, 901ps min, 293ps max; typ from 0.414 V to 1.8 V
|   falling waveform, R_fixture 50.000000, V_fixture 1.800000: 20-80 % time 23.4ns typ, 59.1ns min, 12.2ns max; typ from 1.8 V to 0.414 V
[Pulldown]
|Voltage   I(typ)   I(min)   I(max)
-1.8V     -68.38mA   -32.32mA   -104.4mA
-960mV    -68.38mA   -32.32mA   -104.4mA
-780mV    -66.08mA   -32.32mA   -96.42mA
-660mV    -59.2mA    -32.31mA   -87.22mA
-540mV    -50.22mA   -28.51mA   -74.66mA
0V        0A         -200fA     0A
240mV     18.04mA    9.599mA    29.42mA
480mV     30.68mA    16.02mA    50.95mA
780mV     39.48mA    19.99mA    67.57mA
1.14V     41.99mA    20.78mA    74.01mA
2.82V     44.93mA    22.28mA    79.57mA
3.6V      44.93mA    22.28mA    79.57mA
[GND_clamp]
|Voltage   I(typ)   I(min)   I(max)
-1.8V     -9.908A    -9.683A    -9.994A
-1.2V     -3.383A    -4.084A    -2.934A
-1.16V    -2.841A    -3.655A    -2.294A
-1.12V    -2.299A    -3.226A    -1.656A
-1.04V    -1.218A    -2.369A    -414.2mA
-1V       -684.7mA   -1.941A    -119.2mA
-960mV    -257.2mA   -1.514A    -45.66mA
-920mV    -87.03mA   -1.089A    -28.93mA
-840mV    -19.35mA   -312.8mA   -18.97mA
-800mV    -13.55mA   -132.4mA   -15.49mA
-720mV    -8.042mA   -25.67mA   -9.491mA
1.8V      0A         13.64nA    0A
[POWER_clamp]
|Voltage   I(typ)   I(min)   I(max)
-1.8V     470.8mA    433.7mA    554.6mA
-1.14V    95.25mA    122.7mA    82.82mA
-1.12V    84.97mA    114mA      70.27mA
-1.06V    55.51mA    88.42mA    35.67mA
-1.04V    46.34mA    80.15mA    25.76mA
-1V       29.51mA    64.13mA    10.3mA
-940mV    10.39mA    41.86mA    1.109mA
-900mV    3.624mA    28.77mA    182.8uA
-840mV    490.7uA    13.24mA    11.35uA
-800mV    116.8uA    6.532mA    1.77uA
-740mV    13.2uA     1.724mA    109.3nA
0V        0A         18.75nA    0A
[Ramp]
| variable   typ   min   max
dV/dt_r  0.83152/0.44454n   0.56577/0.89996n   1.02764/0.29254n
dV/dt_f  0.83164/23.34953n   0.56497/59.12076n   1.02770/12.17457n
R_load = 50.000000
[Rising Waveform]
R_fixture= 50.000000
V_fixture= 1.800000
V_fixture_min= 1.600000
V_fixture_max= 2.000000
|time   V(typ)   V(min)   V(max)
0s        413.9mV    656.9mV    287.2mV
2.482ns   413.6mV    656.9mV    372.3mV
2.723ns   412.7mV    656.9mV    660.2mV
3.083ns   416.2mV    656.9mV    1.814V
3.483ns   470.6mV    656.9mV    1.978V
3.924ns   738.4mV    656.7mV    1.994V
4.404ns   1.613V     655.7mV    1.997V
4.885ns   1.778V     654.4mV    1.998V
7.728ns   1.799V     1.578V     2V
19.94ns   1.8V       1.6V       2V
[Falling Waveform]
R_fixture= 50.000000
V_fixture= 1.800000
V_fixture_min= 1.600000
V_fixture_max= 2.000000
|time   V(typ)   V(min)   V(max)
0s        1.8V       1.6V       2V
16.82ns   1.8V       1.6V       1.928V
22.42ns   1.793V     1.6V       1.626V
35.24ns   1.624V     1.597V     575.1mV
52.05ns   1.033V     1.547V     354mV
61.66ns   705.2mV    1.488V     325.3mV
75.28ns   552.8mV    1.366V     305.9mV
112.9ns   449.6mV    944.9mV    290.4mV
149.7ns   425.4mV    776.8mV    287.8mV
398.8ns   413.9mV    656.9mV    287.2mV
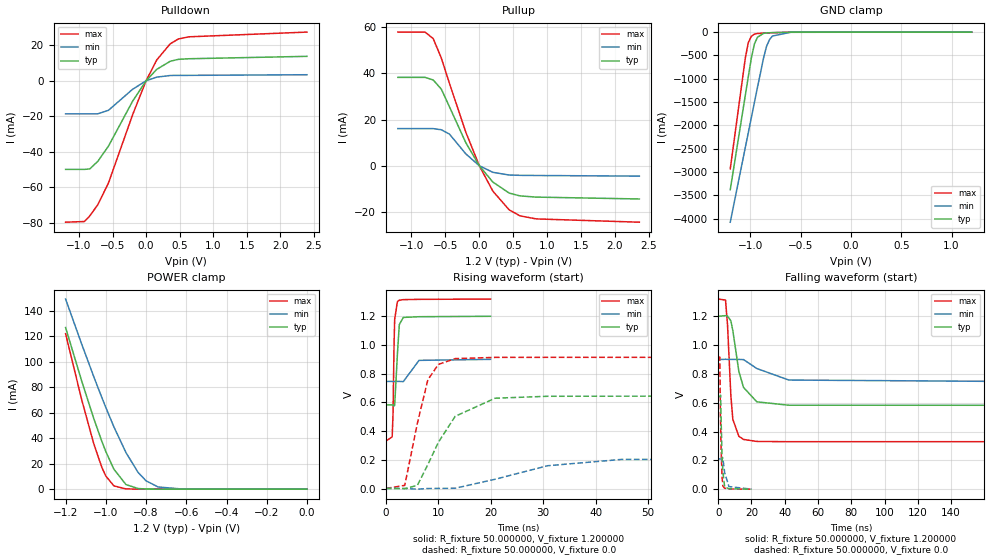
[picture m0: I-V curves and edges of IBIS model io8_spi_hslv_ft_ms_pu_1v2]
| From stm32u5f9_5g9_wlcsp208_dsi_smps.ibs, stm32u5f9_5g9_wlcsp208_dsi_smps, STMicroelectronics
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|   Model io8_spi_hslv_ft_ms_pu_1v2
[Model]  io8_spi_hslv_ft_ms_pu_1v2
Model_type I/O
Polarity   Non-Inverting
Enable   Active-Low
Vinl =   0.360000V
Vinh =   0.840000V
Vmeas =  0.600000V
Cref =   50.000000pF
Rref =   100.000000M
Vref =   0.0V
C_comp   3.133100pF   3.070300pF   3.178200pF
[Temperature Range]   25.000000   0.140000k   -40.000000
[Pullup Reference]   1.200000V   0.900000V   1.320000V
[Pulldown Reference]   0.0V   0.0V   0.0V
[POWER Clamp Reference]   1.200000V   0.900000V   1.320000V
[GND Clamp Reference]   0.0V   0.0V   0.0V
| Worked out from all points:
|   slope of the pulldown table from 0 to 0.18 V, typ, clamps not added: 25.4 ohm
|   slope of the pullup table from 0 to 0.18 V, typ, clamps not added: 27.8 ohm
|   GND clamp passes 1 mA (typ) near -0.51 V on its own axis
|   POWER clamp passes 1 mA (typ) near -0.86 V on its own axis
|   rising waveform, R_fixture 50.000000, V_fixture 1.200000: 20-80 % time 440ps typ, 1.02ns min, 261ps max; typ from 0.583 V to 1.2 V
|   rising waveform, R_fixture 50.000000, V_fixture 0.0: 20-80 % time 5.96ns typ, 13.8ns min, 3.13ns max; typ from 0 V to 0.643 V
|   falling waveform, R_fixture 50.000000, V_fixture 1.200000: 20-80 % time 6.09ns typ, 13.2ns min, 2.68ns max; typ from 1.2 V to 0.583 V
|   falling waveform, R_fixture 50.000000, V_fixture 0.0: 20-80 % time 1.06ns typ, 1.78ns min, 833ps max; typ from 0.643 V to 0 V
[Pulldown]
|Voltage   I(typ)   I(min)   I(max)
-1.2V     -49.85mA   -18.57mA   -79.56mA
-920mV    -49.85mA   -18.57mA   -79.19mA
-840mV    -49.59mA   -18.57mA   -76.08mA
-720mV    -45.32mA   -18.57mA   -69.73mA
-560mV    -36.71mA   -16.58mA   -57.44mA
-200mV    -11.43mA   -4.739mA   -19.03mA
0V        0A         0A         0A
160mV     6.476mA    2.075mA    11.78mA
360mV     10.99mA    2.989mA    20.81mA
480mV     12.07mA    3.053mA    23.52mA
640mV     12.42mA    3.074mA    24.76mA
2.4V      13.77mA    3.423mA    27.42mA
[Pullup]
|Voltage   I(typ)   I(min)   I(max)
-1.2V     38.31mA    16.09mA    57.92mA
-800mV    38.31mA    16.09mA    57.92mA
-680mV    37.17mA    16.09mA    55.11mA
-560mV    33.2mA     15.59mA    46.68mA
-440mV    25.53mA    13.71mA    35.67mA
-200mV    10.05mA    5.175mA    14.59mA
0V        580fA      235pA      0A
200mV     -7.072mA   -2.851mA   -11mA
440mV     -11.84mA   -4.03mA    -19.1mA
600mV     -13.07mA   -4.154mA   -21.71mA
840mV     -13.59mA   -4.223mA   -23.04mA
2.36V     -14.4mA    -4.5mA     -24.46mA
[GND_clamp]
|Voltage   I(typ)   I(min)   I(max)
-1.2V     -3.379A    -4.076A    -2.932A
-1.05V    -1.35A     -2.47A     -550.7mA
-1.02V    -947.8mA   -2.149A    -221.5mA
-990mV    -552.4mA   -1.829A    -88.44mA
-960mV    -255.3mA   -1.51A     -44.87mA
-930mV    -111.8mA   -1.191A    -30.68mA
-870mV    -28.35mA   -564.6mA   -21.34mA
-840mV    -18.65mA   -309.5mA   -18.49mA
-810mV    -14.07mA   -161.6mA   -15.92mA
-780mV    -11.37mA   -83.33mA   -13.53mA
-600mV    -3.009mA   -4.321mA   -3.091mA
1.2V      0A         13.65nA    0A
[POWER_clamp]
|Voltage   I(typ)   I(min)   I(max)
-1.2V     127mA      149.4mA    122.2mA
-1.12V    84.98mA    114mA      70.29mA
-1.06V    55.52mA    88.42mA    35.69mA
-1.02V    37.64mA    72.04mA    17.19mA
-1V       29.52mA    64.13mA    10.33mA
-960mV    15.7mA     48.99mA    2.596mA
-900mV    3.636mA    28.77mA    207.8uA
-840mV    502.9uA    13.24mA    43.46uA
-800mV    129uA      6.535mA    43.46uA
-740mV    26.25uA    1.726mA    43.46uA
-620mV    25.09uA    82.33uA    35.76uA
0V        0A         17.36nA    0A
[Ramp]
| variable   typ   min   max
dV/dt_r  0.38571/5.95214n   0.12565/13.79435n   0.54819/3.11208n
dV/dt_f  0.37035/6.08641n   92.34600m/13.15012n 0.59402/2.66357n
R_load = 50.000000
[Rising Waveform]
R_fixture= 50.000000
V_fixture= 1.200000
V_fixture_min= 0.900000
V_fixture_max= 1.320000
|time   V(typ)   V(min)   V(max)
0s        582.7mV    746.1mV    330mV
1.201ns   582.8mV    746.1mV    360.1mV
1.361ns   580.9mV    746.1mV    512mV
1.562ns   574.7mV    746.1mV    1.008V
1.682ns   580.1mV    746.1mV    1.179V
2.202ns   937.9mV    746.1mV    1.302V
2.563ns   1.142V     746.2mV    1.312V
3.323ns   1.192V     745mV      1.316V
6.326ns   1.197V     892.9mV    1.318V
19.94ns   1.2V       900mV      1.32V
[Rising Waveform]
R_fixture= 50.000000
V_fixture= 0.0
V_fixture_min= 0.0
V_fixture_max= 0.0
|time   V(typ)   V(min)   V(max)
0s        434.2uV    495.9uV    378.8uV
3.604ns   -604.2uV   457.7uV    22.08mV
6.006ns   22.23mV    -4.447mV   454.9mV
8.008ns   167mV      201.5uV    757.9mV
10.01ns   322.3mV    637.2uV    864.9mV
13.21ns   503.1mV    2.031mV    905.1mV
20.82ns   629.2mV    64.71mV    913.7mV
30.83ns   642.7mV    158.8mV    914mV
44.84ns   643.3mV    202.6mV    914mV
199.4ns   643.3mV    210mV      914mV
[Falling Waveform]
R_fixture= 50.000000
V_fixture= 1.200000
V_fixture_min= 0.900000
V_fixture_max= 1.320000
|time   V(typ)   V(min)   V(max)
0s        1.2V       900mV      1.32V
4.404ns   1.205V     902mV      1.313V
5.606ns   1.202V     901.1mV    1.141V
7.608ns   1.169V     901.1mV    650.3mV
8.809ns   1.1V       901.2mV    484.5mV
12.41ns   818mV      900.9mV    367.5mV
15.22ns   706.6mV    899.9mV    345.6mV
23.22ns   606.6mV    837.7mV    331.7mV
42.44ns   583.1mV    757.9mV    329.9mV
199.4ns   582.7mV    746.1mV    330mV
[Falling Waveform]
R_fixture= 50.000000
V_fixture= 0.0
V_fixture_min= 0.0
V_fixture_max= 0.0
|time   V(typ)   V(min)   V(max)
0s        643.3mV    210mV      914mV
961ps     643.4mV    210mV      918.3mV
1.321ns   652.9mV    210.1mV    547.8mV
1.481ns   652.1mV    210.1mV    451.2mV
1.802ns   457.9mV    210.1mV    262.9mV
2.322ns   233.2mV    210mV      84.78mV
2.803ns   124.2mV    217.4mV    21.33mV
3.884ns   15.98mV    114.6mV    7.067mV
6.446ns   3.295mV    18.46mV    1.842mV
19.94ns   434.2uV    495.9uV    378.8uV
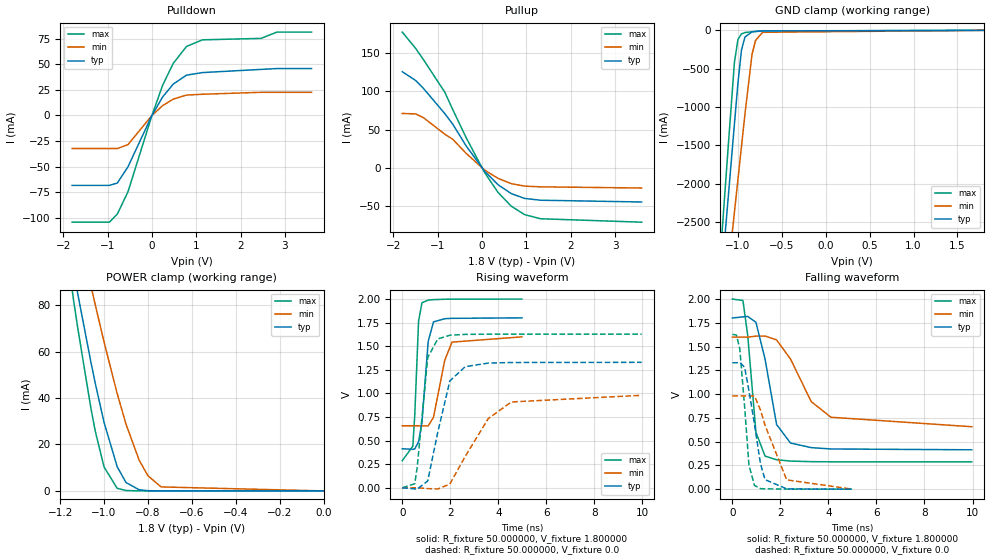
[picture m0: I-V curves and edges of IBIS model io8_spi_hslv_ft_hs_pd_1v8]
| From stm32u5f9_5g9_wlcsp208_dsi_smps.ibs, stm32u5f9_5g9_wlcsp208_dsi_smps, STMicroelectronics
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|   Model io8_spi_hslv_ft_hs_pd_1v8
[Model]  io8_spi_hslv_ft_hs_pd_1v8
Model_type I/O
Polarity   Non-Inverting
Enable   Active-Low
Vinl =   0.540000V
Vinh =   1.260000V
Vmeas =  0.900000V
Cref =   50.000000pF
Rref =   100.000000M
Vref =   0.0V
C_comp   3.338700pF   3.332500pF   3.379000pF
[Temperature Range]   25.000000   0.140000k   -40.000000
[Pullup Reference]   1.800000V   1.600000V   2.000000V
[Pulldown Reference]   0.0V   0.0V   0.0V
[POWER Clamp Reference]   1.800000V   1.600000V   2.000000V
[GND Clamp Reference]   0.0V   0.0V   0.0V
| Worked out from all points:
|   slope of the pulldown table from 0 to 0.27 V, typ, clamps not added: 13.6 ohm
|   slope of the pullup table from 0 to 0.27 V, typ, clamps not added: 15.9 ohm
|   GND clamp passes 1 mA (typ) near -0.50 V on its own axis
|   POWER clamp passes 1 mA (typ) near -0.86 V on its own axis
|   rising waveform, R_fixture 50.000000, V_fixture 1.800000: 20-80 % time 249ps typ, 426ps min, 162ps max; typ from 0.414 V to 1.8 V
|   rising waveform, R_fixture 50.000000, V_fixture 0.0: 20-80 % time 658ps typ, 1.41ns min, 354ps max; typ from 0 V to 1.33 V
|   falling waveform, R_fixture 50.000000, V_fixture 1.800000: 20-80 % time 577ps typ, 1.2ns min, 341ps max; typ from 1.8 V to 0.414 V
|   falling waveform, R_fixture 50.000000, V_fixture 0.0: 20-80 % time 497ps typ, 772ps min, 276ps max; typ from 1.33 V to 0 V
[Pulldown]
|Voltage   I(typ)   I(min)   I(max)
-1.8V     -68.38mA   -32.32mA   -104.4mA
-960mV    -68.38mA   -32.32mA   -104.4mA
-780mV    -66.07mA   -32.32mA   -96.42mA
-540mV    -50.22mA   -28.51mA   -74.66mA
0V        -10fA      -300fA     0A
240mV     18.04mA    9.599mA    29.41mA
480mV     30.68mA    16.02mA    50.95mA
780mV     39.47mA    19.98mA    67.56mA
1.14V     41.99mA    20.78mA    74.01mA
2.46V     45.09mA    22.69mA    75.44mA
2.82V     45.91mA    22.69mA    81.6mA
3.6V      45.91mA    22.69mA    81.6mA
[Pullup]
|Voltage   I(typ)   I(min)   I(max)
-1.8V     125.5mA    71.12mA    177.1mA
-1.5V     114.2mA    70.55mA    156mA
-1.32V    103.6mA    65.57mA    141.1mA
-840mV    70.94mA    44.11mA    98.78mA
-660mV    57.08mA    37.47mA    76.04mA
-360mV    29.01mA    19.22mA    39.75mA
60mV      -4.209mA   -2.643mA   -6.075mA
360mV     -21.65mA   -13.44mA   -31.68mA
660mV     -33.29mA   -20.31mA   -49.69mA
960mV     -39.54mA   -23.52mA   -60.64mA
1.32V     -41.88mA   -24.45mA   -66.02mA
3.6V      -44.2mA    -26mA      -70.5mA
[GND_clamp]
|Voltage   I(typ)   I(min)   I(max)
-1.8V     -9.908A    -9.683A    -9.994A
-1.2V     -3.383A    -4.084A    -2.934A
-1.16V    -2.841A    -3.655A    -2.294A
-1.12V    -2.299A    -3.226A    -1.656A
-1.04V    -1.218A    -2.369A    -414.2mA
-1V       -684.7mA   -1.941A    -119.2mA
-960mV    -257.2mA   -1.514A    -45.67mA
-920mV    -87.04mA   -1.089A    -28.94mA
-840mV    -19.36mA   -312.8mA   -18.98mA
-800mV    -13.56mA   -132.4mA   -15.51mA
-720mV    -8.053mA   -25.67mA   -9.504mA
1.8V      45.71uA    33.32uA    56.11uA
[POWER_clamp]
|Voltage   I(typ)   I(min)   I(max)
-1.8V     470.8mA    433.7mA    554.6mA
-1.14V    95.25mA    122.7mA    82.82mA
-1.12V    84.97mA    114mA      70.27mA
-1.06V    55.51mA    88.42mA    35.67mA
-1.04V    46.34mA    80.15mA    25.76mA
-1V       29.51mA    64.13mA    10.3mA
-940mV    10.39mA    41.86mA    1.109mA
-900mV    3.624mA    28.77mA    182.8uA
-840mV    490.7uA    13.24mA    11.35uA
-800mV    116.8uA    6.532mA    1.77uA
-740mV    13.2uA     1.724mA    109.3nA
0V        0A         18.75nA    0A
[Ramp]
| variable   typ   min   max
dV/dt_r  0.79734/0.65649n   0.58754/1.41187n   0.97632/0.35392n
dV/dt_f  0.83139/0.57633n   0.56465/1.19978n   1.02743/0.34014n
R_load = 50.000000
[Rising Waveform]
R_fixture= 50.000000
V_fixture= 1.800000
V_fixture_min= 1.600000
V_fixture_max= 2.000000
|time   V(typ)   V(min)   V(max)
0s        413.9mV    656.5mV    287.2mV
440.4ps   407.7mV    656.7mV    441.2mV
520.5ps   412.3mV    656.7mV    765.6mV
680.7ps   487.5mV    656.6mV    1.767V
820.8ps   693.8mV    655mV      1.96V
1.081ns   1.551V     655.9mV    1.988V
1.301ns   1.757V     746.7mV    1.993V
1.772ns   1.791V     1.353V     1.997V
2.072ns   1.795V     1.543V     1.998V
4.985ns   1.8V       1.599V     1.999V
[Rising Waveform]
R_fixture= 50.000000
V_fixture= 0.0
V_fixture_min= 0.0
V_fixture_max= 0.0
|time   V(typ)   V(min)   V(max)
0s        -19.93uV   -4.875uV   106uV
520.5ps   -11.43mV   28.87uV    43.55mV
620.6ps   -14.28mV   120.4uV    212.2mV
1.061ns   73.28mV    -8.228mV   1.38V
1.481ns   590.9mV    -12.19mV   1.577V
1.982ns   1.132V     39.23mV    1.616V
2.623ns   1.283V     332.8mV    1.625V
3.584ns   1.321V     733.8mV    1.627V
4.545ns   1.327V     909.3mV    1.627V
9.97ns    1.329V     979.8mV    1.627V
[Falling Waveform]
R_fixture= 50.000000
V_fixture= 1.800000
V_fixture_min= 1.600000
V_fixture_max= 2.000000
|time   V(typ)   V(min)   V(max)
0s        1.8V       1.599V     1.999V
440.4ps   1.812V     1.599V     1.984V
640.6ps   1.816V     1.599V     1.613V
981ps     1.755V     1.609V     599mV
1.361ns   1.368V     1.61V      347.5mV
1.842ns   679.2mV    1.569V     309.3mV
2.422ns   485mV      1.368V     295.3mV
3.283ns   436.7mV    920.8mV    289.3mV
4.104ns   422.7mV    756.3mV    287.8mV
9.97ns    413.9mV    656.5mV    287.2mV
[Falling Waveform]
R_fixture= 50.000000
V_fixture= 0.0
V_fixture_min= 0.0
V_fixture_max= 0.0
|time   V(typ)   V(min)   V(max)
0s        1.329V     979.8mV    1.627V
170.2ps   1.329V     979.8mV    1.621V
310.3ps   1.332V     979.9mV    1.473V
510.5ps   1.281V     979.8mV    865.4mV
690.7ps   1.035V     981.2mV    252mV
920.9ps   681.8mV    979.7mV    39.82mV
1.171ns   266.5mV    832.8mV    5.68mV
1.361ns   99.85mV    671.2mV    3.655mV
2.262ns   2.877mV    97.7mV     733.6uV
4.985ns   -19.93uV   -4.875uV   106uV
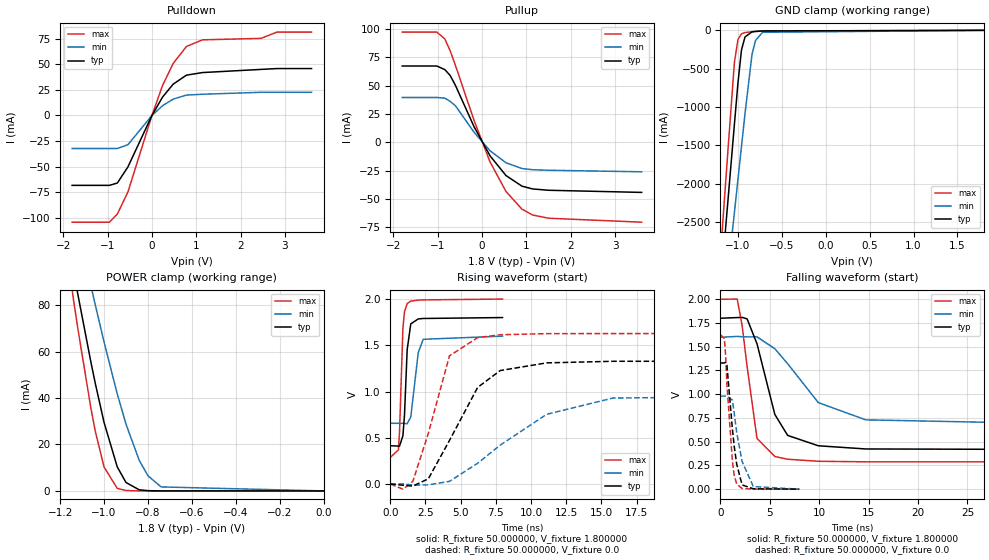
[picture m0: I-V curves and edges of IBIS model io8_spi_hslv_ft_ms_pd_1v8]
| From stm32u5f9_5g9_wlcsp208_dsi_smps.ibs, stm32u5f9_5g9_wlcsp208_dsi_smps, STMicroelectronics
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|   Model io8_spi_hslv_ft_ms_pd_1v8
[Model]  io8_spi_hslv_ft_ms_pd_1v8
Model_type I/O
Polarity   Non-Inverting
Enable   Active-Low
Vinl =   0.540000V
Vinh =   1.260000V
Vmeas =  0.900000V
Cref =   50.000000pF
Rref =   100.000000M
Vref =   0.0V
C_comp   3.338700pF   3.332500pF   3.379000pF
[Temperature Range]   25.000000   0.140000k   -40.000000
[Pullup Reference]   1.800000V   1.600000V   2.000000V
[Pulldown Reference]   0.0V   0.0V   0.0V
[POWER Clamp Reference]   1.800000V   1.600000V   2.000000V
[GND Clamp Reference]   0.0V   0.0V   0.0V
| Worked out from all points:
|   slope of the pulldown table from 0 to 0.27 V, typ, clamps not added: 13.6 ohm
|   slope of the pullup table from 0 to 0.27 V, typ, clamps not added: 15.9 ohm
|   GND clamp passes 1 mA (typ) near -0.50 V on its own axis
|   POWER clamp passes 1 mA (typ) near -0.86 V on its own axis
|   rising waveform, R_fixture 50.000000, V_fixture 1.800000: 20-80 % time 241ps typ, 385ps min, 215ps max; typ from 0.414 V to 1.8 V
|   rising waveform, R_fixture 50.000000, V_fixture 0.0: 20-80 % time 2.75ns typ, 5.57ns min, 1.64ns max; typ from 0 V to 1.33 V
|   falling waveform, R_fixture 50.000000, V_fixture 1.800000: 20-80 % time 2.12ns typ, 4.8ns min, 1.23ns max; typ from 1.8 V to 0.414 V
|   falling waveform, R_fixture 50.000000, V_fixture 0.0: 20-80 % time 788ps typ, 1.06ns min, 618ps max; typ from 1.33 V to 0 V
[Pulldown]
|Voltage   I(typ)   I(min)   I(max)
-1.8V     -68.38mA   -32.32mA   -104.4mA
-960mV    -68.38mA   -32.32mA   -104.4mA
-780mV    -66.07mA   -32.32mA   -96.42mA
-540mV    -50.22mA   -28.51mA   -74.66mA
0V        -10fA      -300fA     0A
240mV     18.04mA    9.599mA    29.41mA
480mV     30.68mA    16.02mA    50.95mA
780mV     39.47mA    19.98mA    67.56mA
1.14V     41.99mA    20.78mA    74.01mA
2.46V     45.09mA    22.69mA    75.44mA
2.82V     45.91mA    22.69mA    81.6mA
3.6V      45.91mA    22.69mA    81.6mA
[Pullup]
|Voltage   I(typ)   I(min)   I(max)
-1.8V     67.41mA    39.62mA    97.36mA
-1.02V    67.41mA    39.62mA    97.36mA
-840mV    64.23mA    39.02mA    91.37mA
-720mV    59.09mA    36.19mA    80.99mA
-600mV    50.28mA    32.32mA    67.95mA
-180mV    13.77mA    8.913mA    19.32mA
180mV     -11.9mA    -7.442mA   -17.26mA
540mV     -29.31mA   -18.02mA   -43.36mA
900mV     -38.69mA   -23.13mA   -58.99mA
1.14V     -41.14mA   -24.16mA   -64.17mA
1.5V      -42.31mA   -24.64mA   -67mA
3.6V      -44.2mA    -26mA      -70.5mA
[GND_clamp]
|Voltage   I(typ)   I(min)   I(max)
-1.8V     -9.908A    -9.683A    -9.994A
-1.2V     -3.383A    -4.084A    -2.934A
-1.16V    -2.841A    -3.655A    -2.294A
-1.12V    -2.299A    -3.226A    -1.656A
-1.04V    -1.218A    -2.369A    -414.2mA
-1V       -684.7mA   -1.941A    -119.2mA
-960mV    -257.2mA   -1.514A    -45.67mA
-920mV    -87.04mA   -1.089A    -28.94mA
-840mV    -19.36mA   -312.8mA   -18.98mA
-800mV    -13.56mA   -132.4mA   -15.51mA
-720mV    -8.053mA   -25.67mA   -9.504mA
1.8V      45.71uA    33.32uA    56.11uA
[POWER_clamp]
|Voltage   I(typ)   I(min)   I(max)
-1.8V     470.8mA    433.7mA    554.6mA
-1.14V    95.25mA    122.7mA    82.82mA
-1.12V    84.97mA    114mA      70.27mA
-1.06V    55.51mA    88.42mA    35.67mA
-1.04V    46.34mA    80.15mA    25.76mA
-1V       29.51mA    64.13mA    10.3mA
-940mV    10.39mA    41.86mA    1.109mA
-900mV    3.624mA    28.77mA    182.8uA
-840mV    490.7uA    13.24mA    11.35uA
-800mV    116.8uA    6.532mA    1.77uA
-740mV    13.2uA     1.724mA    109.3nA
0V        0A         18.75nA    0A
[Ramp]
| variable   typ   min   max
dV/dt_r  0.79740/2.74642n   0.58783/5.56421n   0.97632/1.63669n
dV/dt_f  0.83141/2.11458n   0.56582/4.79102n   1.02743/1.22635n
R_load = 50.000000
[Rising Waveform]
R_fixture= 50.000000
V_fixture= 1.800000
V_fixture_min= 1.600000
V_fixture_max= 2.000000
|time   V(typ)   V(min)   V(max)
0s        413.8mV    656.5mV    287.1mV
576.6ps   410.3mV    656.6mV    369mV
656.7ps   410mV      656.6mV    561.7mV
896.9ps   521.4mV    656.2mV    1.683V
1.009ns   744.6mV    654.3mV    1.863V
1.201ns   1.454V     652.2mV    1.952V
1.457ns   1.732V     725.6mV    1.978V
1.986ns   1.785V     1.42V      1.988V
2.338ns   1.79V      1.565V     1.991V
7.976ns   1.8V       1.599V     2V
[Rising Waveform]
R_fixture= 50.000000
V_fixture= 0.0
V_fixture_min= 0.0
V_fixture_max= 0.0
|time   V(typ)   V(min)   V(max)
0s        -1.604uV   -2.138uV   -8.119uV
900.9ps   -13.11mV   220uV      -55.74mV
1.602ns   -22.34mV   -11.9mV    28.44mV
2.703ns   56.34mV    -9.076mV   548mV
4.204ns   470.8mV    28.7mV     1.386V
6.206ns   1.045V     224.7mV    1.583V
7.808ns   1.227V     420.6mV    1.614V
11.11ns   1.31V      753.8mV    1.626V
15.82ns   1.327V     929.7mV    1.627V
49.85ns   1.329V     979.8mV    1.627V
[Falling Waveform]
R_fixture= 50.000000
V_fixture= 1.800000
V_fixture_min= 1.600000
V_fixture_max= 2.000000
|time   V(typ)   V(min)   V(max)
0s        1.8V       1.599V     2V
1.702ns   1.807V     1.609V     2.002V
2.202ns   1.809V     1.605V     1.72V
2.703ns   1.793V     1.604V     1.291V
3.704ns   1.531V     1.604V     534.4mV
5.506ns   787.3mV    1.479V     344.1mV
6.807ns   565.9mV    1.321V     315.2mV
9.91ns    457mV      911.3mV    293.8mV
14.71ns   423.4mV    730mV      287.9mV
49.85ns   413.8mV    656.5mV    287.1mV
[Falling Waveform]
R_fixture= 50.000000
V_fixture= 0.0
V_fixture_min= 0.0
V_fixture_max= 0.0
|time   V(typ)   V(min)   V(max)
0s        1.329V     979.8mV    1.627V
400.4ps   1.329V     979.9mV    1.586V
512.5ps   1.335V     979.9mV    1.434V
656.7ps   1.307V     979.8mV    1.104V
1.217ns   629.9mV    937.9mV    293.7mV
1.393ns   455.5mV    801mV      148.3mV
1.65ns    263mV      595.4mV    54.68mV
2.194ns   44.89mV    292.2mV    7.173mV
3.331ns   4.018mV    27.52mV    1.288mV
7.976ns   -1.604uV   -2.138uV   -8.119uV
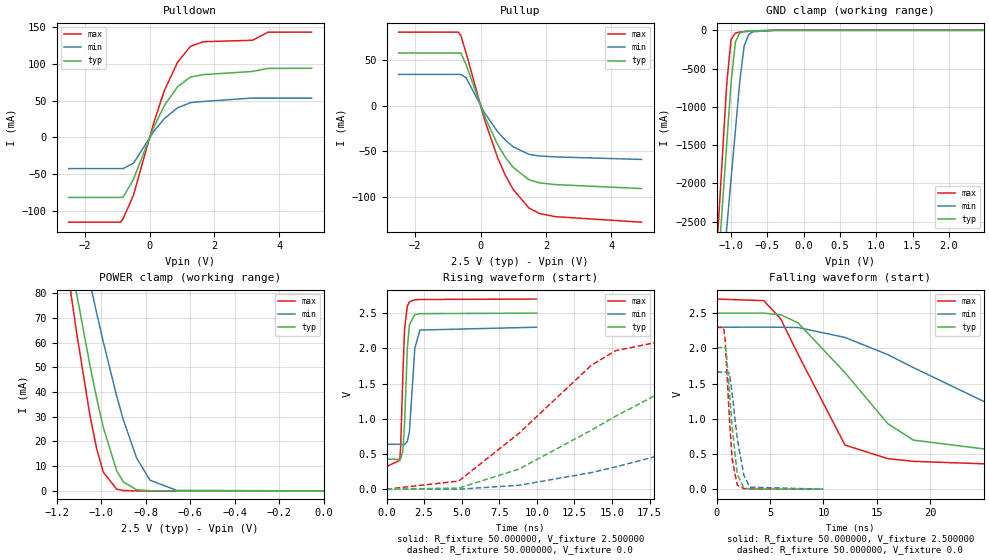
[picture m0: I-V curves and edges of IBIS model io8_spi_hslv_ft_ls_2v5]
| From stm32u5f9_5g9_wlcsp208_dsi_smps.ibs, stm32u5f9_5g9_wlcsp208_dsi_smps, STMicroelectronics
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|   Model io8_spi_hslv_ft_ls_2v5
[Model]  io8_spi_hslv_ft_ls_2v5
Model_type I/O
Polarity   Non-Inverting
Enable   Active-Low
Vinl =   0.750000V
Vinh =   1.750000V
Vmeas =  1.250000V
Cref =   50.000000pF
Rref =   100.000000M
Vref =   0.0V
C_comp   3.438200pF   3.436700pF   3.473300pF
[Temperature Range]   25.000000   0.140000k   -40.000000
[Pullup Reference]   2.500000V   2.300000V   2.700000V
[Pulldown Reference]   0.0V   0.0V   0.0V
[POWER Clamp Reference]   2.500000V   2.300000V   2.700000V
[GND Clamp Reference]   0.0V   0.0V   0.0V
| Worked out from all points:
|   slope of the pulldown table from 0 to 0.375 V, typ, clamps not added: 10.1 ohm
|   slope of the pullup table from 0 to 0.375 V, typ, clamps not added: 11.7 ohm
|   GND clamp passes 1 mA (typ) near -0.50 V on its own axis
|   POWER clamp passes 1 mA (typ) near -0.86 V on its own axis
|   rising waveform, R_fixture 50.000000, V_fixture 2.500000: 20-80 % time 224ps typ, 271ps min, 220ps max; typ from 0.428 V to 2.5 V
|   rising waveform, R_fixture 50.000000, V_fixture 0.0: 20-80 % time 10.5ns typ, 19ns min, 7.03ns max; typ from 0 V to 2.01 V
|   falling waveform, R_fixture 50.000000, V_fixture 2.500000: 20-80 % time 6.96ns typ, 13.5ns min, 4.47ns max; typ from 2.5 V to 0.428 V
|   falling waveform, R_fixture 50.000000, V_fixture 0.0: 20-80 % time 654ps typ, 863ps min, 534ps max; typ from 2.01 V to 0 V
[Pulldown]
|Voltage   I(typ)   I(min)   I(max)
-2.5V     -81.62mA   -42.31mA   -115.3mA
-900mV    -81.62mA   -42.31mA   -115.3mA
-820mV    -81.42mA   -42.31mA   -110.6mA
-500mV    -56.95mA   -35.08mA   -78.57mA
140mV     15.18mA    9.02mA     22.02mA
460mV     44mA       25.98mA    64.38mA
860mV     68.91mA    40.27mA    102.2mA
1.26V     82.21mA    47.42mA    124mA
1.66V     85.53mA    48.99mA    130.3mA
3.18V     89.84mA    53.65mA    132.3mA
3.66V     94.05mA    53.65mA    143.4mA
5V        94.05mA    53.65mA    143.4mA
[Pullup]
|Voltage   I(typ)   I(min)   I(max)
-2.5V     58.05mA    34.52mA    81.07mA
-680mV    58.05mA    34.52mA    81.07mA
-600mV    58.05mA    34.52mA    77.18mA
-440mV    45.11mA    30.86mA    58.07mA
120mV     -11.18mA   -7.509mA   -14.95mA
520mV     -42.31mA   -28.36mA   -56.92mA
760mV     -56.64mA   -37.85mA   -76.55mA
1V        -67.83mA   -45.14mA   -92.22mA
1.48V     -81.29mA   -53.4mA    -112.4mA
1.8V      -84.73mA   -55.19mA   -118.5mA
2.28V     -86.63mA   -56.16mA   -121.9mA
4.92V     -91mA      -59mA      -128mA
[GND_clamp]
|Voltage   I(typ)   I(min)   I(max)
-2.5V     -9.641A    -9.693A    -9.352A
-1.18V    -3.114A    -3.874A    -2.614A
-1.12V    -2.301A    -3.23A     -1.656A
-1.06V    -1.489A    -2.587A    -706.2mA
-1V       -685.8mA   -1.945A    -119.3mA
-940mV    -149.7mA   -1.304A    -34.73mA
-880mV    -35.54mA   -672.6mA   -23.06mA
-820mV    -16.19mA   -206.4mA   -17.27mA
-760mV    -10.58mA   -57.55mA   -12.41mA
-700mV    -7.152mA   -18.74mA   -8.24mA
-400mV    -103.3uA   -378.5uA   -41.74uA
2.48V     0A         13.22nA    0A
[POWER_clamp]
|Voltage   I(typ)   I(min)   I(max)
-2.49V    881mA      773.1mA    1.07A
-1.14V    95.25mA    122.7mA    82.82mA
-1.11V    79.9mA     109.7mA    64.14mA
-1.05V    50.87mA    84.26mA    30.57mA
-1.02V    37.63mA    72.04mA    17.17mA
-990mV    25.71mA    60.25mA    7.621mA
-930mV    8.217mA    38.43mA    713.9uA
-900mV    3.624mA    28.77mA    182.8uA
-840mV    490.7uA    13.24mA    11.35uA
-780mV    56.55uA    4.324mA    699nA
-660mV    716.7nA    226uA      9.786nA
0V        0A         19.53nA    0A
[Ramp]
| variable   typ   min   max
dV/dt_r  1.20666/10.50122n   0.99780/18.93880n   1.37784/7.01640n
dV/dt_f  1.24344/6.94406n   0.99746/13.52853n   1.42636/4.46165n
R_load = 50.000000
[Rising Waveform]
R_fixture= 50.000000
V_fixture= 2.500000
V_fixture_min= 2.300000
V_fixture_max= 2.700000
|time   V(typ)   V(min)   V(max)
0s        427.6mV    637.6mV    322.7mV
880.9ps   422.9mV    637.6mV    408.5mV
940.9ps   431.2mV    637.5mV    606.5mV
1.081ns   531mV      635.5mV    1.584V
1.201ns   938.3mV    633.9mV    2.273V
1.381ns   1.987V     678.1mV    2.6V
1.522ns   2.337V     809.2mV    2.661V
1.882ns   2.48V      2.002V     2.69V
2.222ns   2.493V     2.26V      2.694V
9.97ns    2.5V       2.3V       2.7V
[Rising Waveform]
R_fixture= 50.000000
V_fixture= 0.0
V_fixture_min= 0.0
V_fixture_max= 0.0
|time   V(typ)   V(min)   V(max)
0s        2.134nV    120.5nV    2.162nV
4.805ns   15.14mV    -19.65uV   115.1mV
8.809ns   284.7mV    54.83mV    793.6mV
13.61ns   835.7mV    234.7mV    1.757V
15.22ns   1.033V     315.4mV    1.966V
20.02ns   1.571V     581mV      2.174V
24.02ns   1.791V     810.8mV    2.235V
36.44ns   1.964V     1.387V     2.288V
54.45ns   2.005V     1.595V     2.296V
199.4ns   2.011V     1.663V     2.296V
[Falling Waveform]
R_fixture= 50.000000
V_fixture= 2.500000
V_fixture_min= 2.300000
V_fixture_max= 2.700000
|time   V(typ)   V(min)   V(max)
0s        2.5V       2.3V       2.7V
4.404ns   2.5V       2.301V     2.678V
6.006ns   2.476V     2.3V       2.418V
7.608ns   2.364V     2.296V     1.92V
12.01ns   1.655V     2.155V     626.1mV
16.02ns   928.8mV    1.91V      433.3mV
18.42ns   696.3mV    1.725V     395.1mV
28.83ns   499.1mV    966.5mV    339.5mV
46.85ns   442.7mV    723.7mV    324.8mV
199.4ns   427.6mV    637.6mV    322.7mV
[Falling Waveform]
R_fixture= 50.000000
V_fixture= 0.0
V_fixture_min= 0.0
V_fixture_max= 0.0
|time   V(typ)   V(min)   V(max)
0s        2.011V     1.663V     2.296V
660.7ps   2.011V     1.663V     2.295V
800.8ps   2.019V     1.663V     2.134V
900.9ps   1.964V     1.663V     1.86V
1.201ns   1.397V     1.647V     1.013V
1.461ns   882.3mV    1.366V     424.3mV
1.942ns   208.1mV    709.5mV    56.72mV
2.563ns   19.14mV    194.2mV    7.611mV
3.123ns   4.044mV    28.21mV    3.648mV
9.97ns    2.134nV    120.5nV    2.162nV
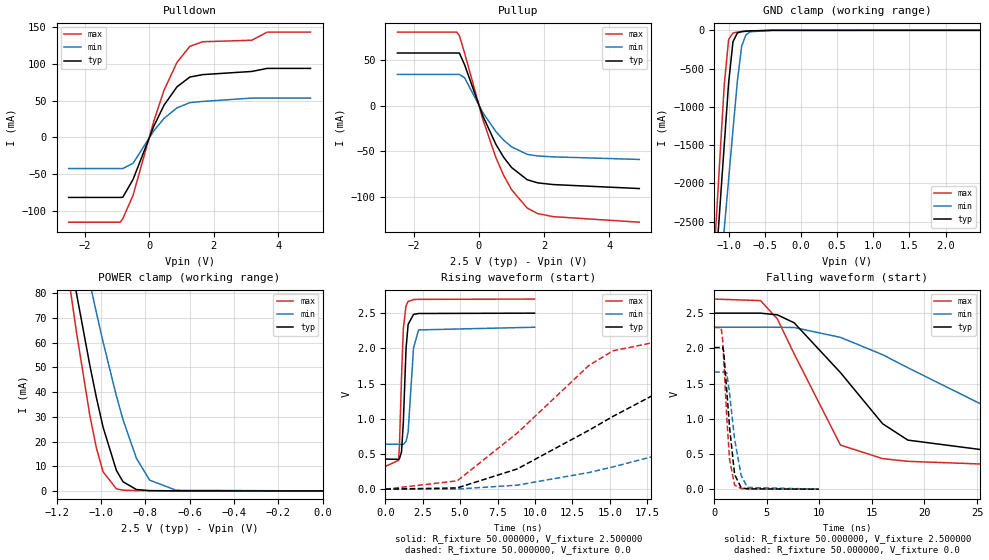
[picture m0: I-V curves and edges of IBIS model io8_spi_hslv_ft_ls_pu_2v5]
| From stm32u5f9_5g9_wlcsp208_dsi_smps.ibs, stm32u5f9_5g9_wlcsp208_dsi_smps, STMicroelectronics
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|   Model io8_spi_hslv_ft_ls_pu_2v5
[Model]  io8_spi_hslv_ft_ls_pu_2v5
Model_type I/O
Polarity   Non-Inverting
Enable   Active-Low
Vinl =   0.750000V
Vinh =   1.750000V
Vmeas =  1.250000V
Cref =   50.000000pF
Rref =   100.000000M
Vref =   0.0V
C_comp   3.438200pF   3.436700pF   3.473300pF
[Temperature Range]   25.000000   0.140000k   -40.000000
[Pullup Reference]   2.500000V   2.300000V   2.700000V
[Pulldown Reference]   0.0V   0.0V   0.0V
[POWER Clamp Reference]   2.500000V   2.300000V   2.700000V
[GND Clamp Reference]   0.0V   0.0V   0.0V
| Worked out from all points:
|   slope of the pulldown table from 0 to 0.375 V, typ, clamps not added: 10.1 ohm
|   slope of the pullup table from 0 to 0.375 V, typ, clamps not added: 11.7 ohm
|   GND clamp passes 1 mA (typ) near -0.50 V on its own axis
|   POWER clamp passes 1 mA (typ) near -0.85 V on its own axis
|   rising waveform, R_fixture 50.000000, V_fixture 2.500000: 20-80 % time 223ps typ, 270ps min, 219ps max; typ from 0.428 V to 2.5 V
|   rising waveform, R_fixture 50.000000, V_fixture 0.0: 20-80 % time 10.5ns typ, 19ns min, 7.04ns max; typ from 0 V to 2.01 V
|   falling waveform, R_fixture 50.000000, V_fixture 2.500000: 20-80 % time 6.96ns typ, 13.6ns min, 4.47ns max; typ from 2.5 V to 0.428 V
|   falling waveform, R_fixture 50.000000, V_fixture 0.0: 20-80 % time 657ps typ, 866ps min, 536ps max; typ from 2.01 V to 0 V
[Pulldown]
|Voltage   I(typ)   I(min)   I(max)
-2.5V     -81.61mA   -42.31mA   -115.3mA
-900mV    -81.61mA   -42.31mA   -115.3mA
-820mV    -81.42mA   -42.31mA   -110.6mA
-500mV    -56.95mA   -35.08mA   -78.57mA
140mV     15.18mA    9.02mA     22.02mA
460mV     44mA       25.98mA    64.37mA
860mV     68.91mA    40.27mA    102.2mA
1.26V     82.21mA    47.42mA    124mA
1.66V     85.53mA    48.99mA    130.3mA
3.18V     89.84mA    53.63mA    132.3mA
3.66V     94mA       53.63mA    143.4mA
5V        94mA       53.63mA    143.4mA
[Pullup]
|Voltage   I(typ)   I(min)   I(max)
-2.5V     58.04mA    34.52mA    81.05mA
-680mV    58.04mA    34.52mA    81.05mA
-600mV    58.04mA    34.52mA    77.16mA
-440mV    45.11mA    30.86mA    58.07mA
120mV     -11.17mA   -7.509mA   -14.95mA
520mV     -42.31mA   -28.36mA   -56.92mA
760mV     -56.64mA   -37.85mA   -76.55mA
1V        -67.83mA   -45.13mA   -92.22mA
1.48V     -81.29mA   -53.4mA    -112.4mA
1.8V      -84.73mA   -55.19mA   -118.5mA
2.28V     -86.63mA   -56.16mA   -121.9mA
4.92V     -91mA      -59mA      -128mA
[GND_clamp]
|Voltage   I(typ)   I(min)   I(max)
-2.5V     -9.641A    -9.693A    -9.352A
-1.18V    -3.114A    -3.874A    -2.614A
-1.12V    -2.301A    -3.23A     -1.656A
-1.06V    -1.489A    -2.587A    -706.2mA
-1V       -685.8mA   -1.945A    -119.3mA
-940mV    -149.7mA   -1.304A    -34.73mA
-880mV    -35.54mA   -672.6mA   -23.06mA
-820mV    -16.19mA   -206.4mA   -17.27mA
-760mV    -10.58mA   -57.55mA   -12.41mA
-700mV    -7.152mA   -18.74mA   -8.24mA
-400mV    -103.3uA   -378.5uA   -41.74uA
2.48V     0A         13.22nA    0A
[POWER_clamp]
|Voltage   I(typ)   I(min)   I(max)
-2.49V    881.1mA    773.1mA    1.07A
-1.14V    95.32mA    122.8mA    82.93mA
-1.11V    79.97mA    109.7mA    64.26mA
-1.05V    50.95mA    84.3mA     30.69mA
-1.02V    37.7mA     72.08mA    17.29mA
-990mV    25.79mA    60.29mA    7.738mA
-930mV    8.312mA    38.47mA    853.1uA
-900mV    3.712mA    28.81mA    313.6uA
-840mV    566.2uA    13.29mA    123.7uA
-780mV    119.1uA    4.365mA    94.04uA
-660mV    38.99uA    251.5uA    57.77uA
0V        0A         18.92nA    0A
[Ramp]
| variable   typ   min   max
dV/dt_r  1.20650/10.51121n   0.99765/18.95666n   1.37763/7.02242n
dV/dt_f  1.24312/6.94746n   0.99707/13.54914n   1.42607/4.46321n
R_load = 50.000000
[Rising Waveform]
R_fixture= 50.000000
V_fixture= 2.500000
V_fixture_min= 2.300000
V_fixture_max= 2.700000
|time   V(typ)   V(min)   V(max)
0s        428.1mV    638.2mV    323.2mV
880.9ps   423.5mV    638.2mV    409.3mV
940.9ps   431.8mV    638.1mV    607.9mV
1.081ns   531.8mV    636.2mV    1.588V
1.201ns   940.1mV    634.6mV    2.279V
1.381ns   1.992V     678.8mV    2.604V
1.522ns   2.34V      810.1mV    2.665V
1.882ns   2.482V     2.005V     2.693V
2.222ns   2.495V     2.262V     2.696V
9.97ns    2.5V       2.3V       2.7V
[Rising Waveform]
R_fixture= 50.000000
V_fixture= 0.0
V_fixture_min= 0.0
V_fixture_max= 0.0
|time   V(typ)   V(min)   V(max)
0s        472uV      557.8uV    453.4uV
4.805ns   18.26mV    2.429mV    118.8mV
8.809ns   287.4mV    57.16mV    796.6mV
13.61ns   837.9mV    236.9mV    1.759V
15.22ns   1.035V     317.5mV    1.966V
20.02ns   1.573V     582.8mV    2.173V
24.02ns   1.792V     812.3mV    2.235V
37.24ns   1.967V     1.408V     2.289V
57.26ns   2.007V     1.608V     2.296V
199.4ns   2.011V     1.663V     2.296V
[Falling Waveform]
R_fixture= 50.000000
V_fixture= 2.500000
V_fixture_min= 2.300000
V_fixture_max= 2.700000
|time   V(typ)   V(min)   V(max)
0s        2.5V       2.3V       2.7V
4.404ns   2.5V       2.301V     2.678V
6.006ns   2.476V     2.3V       2.419V
7.608ns   2.363V     2.296V     1.921V
12.01ns   1.656V     2.156V     627mV
16.02ns   929.7mV    1.91V      434mV
18.42ns   697mV      1.725V     395.8mV
28.43ns   503.4mV    982.7mV    340.7mV
44.44ns   445.7mV    737.8mV    325.9mV
199.4ns   428.1mV    638.2mV    323.2mV
[Falling Waveform]
R_fixture= 50.000000
V_fixture= 0.0
V_fixture_min= 0.0
V_fixture_max= 0.0
|time   V(typ)   V(min)   V(max)
0s        2.011V     1.663V     2.296V
660.7ps   2.011V     1.663V     2.295V
800.8ps   2.019V     1.663V     2.134V
900.9ps   1.964V     1.663V     1.86V
1.201ns   1.397V     1.648V     1.015V
1.461ns   884.5mV    1.365V     428mV
1.942ns   211.1mV    710.7mV    58.31mV
2.563ns   19.9mV     196.7mV    9.398mV
3.163ns   4.588mV    24.93mV    5.722mV
9.97ns    472uV      557.8uV    453.4uV
